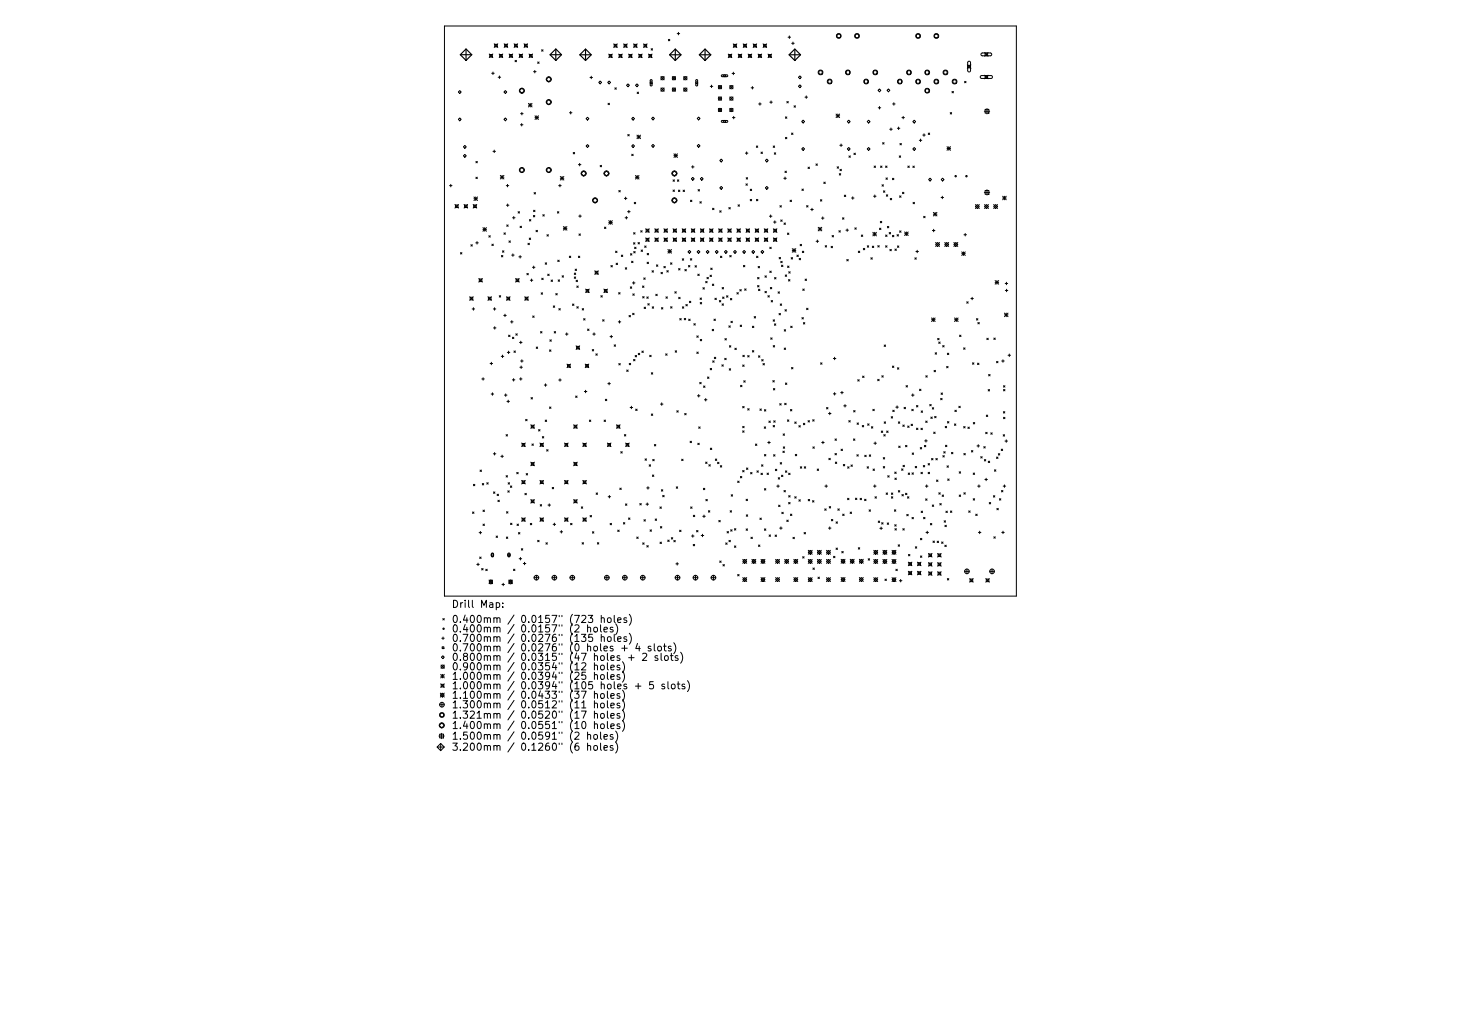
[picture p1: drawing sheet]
<svg xmlns="http://www.w3.org/2000/svg" width="297mm" height="210mm" viewBox="0 0 297 210" stroke-linecap="round" stroke-linejoin="round" font-family="sans-serif">
<defs><g id="words">
<g font-size="2">
<text x="91.8" y="123.6">Drill Map:</text>
<text x="91.8" y="126.7">0.400mm / 0.0157&quot; (723 holes)</text>
<text x="91.8" y="128.6">0.400mm / 0.0157&quot; (2 holes)</text>
<text x="91.8" y="130.5">0.700mm / 0.0276&quot; (135 holes)</text>
<text x="91.8" y="132.4">0.700mm / 0.0276&quot; (0 holes + 4 slots)</text>
<text x="91.8" y="134.4">0.800mm / 0.0315&quot; (47 holes + 2 slots)</text>
<text x="91.8" y="136.3">0.900mm / 0.0354&quot; (12 holes)</text>
<text x="91.8" y="138.2">1.000mm / 0.0394&quot; (25 holes)</text>
<text x="91.8" y="140.1">1.000mm / 0.0394&quot; (105 holes + 5 slots)</text>
<text x="91.8" y="142.1">1.100mm / 0.0433&quot; (37 holes)</text>
<text x="91.8" y="144">1.300mm / 0.0512&quot; (11 holes)</text>
<text x="91.8" y="146.1">1.321mm / 0.0520&quot; (17 holes)</text>
<text x="91.8" y="148.2">1.400mm / 0.0551&quot; (10 holes)</text>
<text x="91.8" y="150.4">1.500mm / 0.0591&quot; (2 holes)</text>
<text x="91.8" y="152.6">3.200mm / 0.1260&quot; (6 holes)</text>
</g>
</g></defs>
<g fill="none" stroke="#000" stroke-width=".2">
<path d="M90.4 5.3h116.2v115.9h-116.2zM93.5 18.4l.3 .3-.3 .3-.3-.3zM99.5 11l.7 .7M99.6 11.1h.5v.5h-.5zM100 14.9h.5M100.2 11l-.7 .7M100.2 14.6v.6M100.5 8.9l.7 .7M100.6 9h.5v.5h-.5zM101.2 8.9l-.7 .7M101.3 15.7h.5M101.5 11l.7 .7"/>
<path d="M101.5 15.4v.6M101.6 11.1h.5v.5h-.5zM102.2 11l-.7 .7M102.5 8.9l.7 .7M102.6 9h.5v.5h-.5zM102.7 18.4l.3 .3-.3 .3-.2-.3zM103.2 8.9l-.7 .7M103.5 11l.7 .7M103.6 11.1h.5v.5h-.5zM104.2 11l-.7 .7M104.5 8.9l.8 .7M104.6 9h.5v.5h-.5z"/>
<path d="M104.7 12.3l.3 .3M105 12.3l-.3 .3M105.3 8.9l-.8 .7M105.5 11l.8 .7M105.6 18.4l.5-.5 .5 .5-.5 .6zM105.6 11.1h.6v.5h-.6zM106.3 11l-.8 .7M106.5 8.9l.8 .7M106.7 9h.5v.5h-.5zM107.3 8.9l-.8 .7M107.6 11l.7 .7M107.7 11.1h.5v.5h-.5z"/>
<path d="M108.3 11l-.7 .7M108.5 14.6h.5M108.7 14.3v.5M109.3 12.6l.3 .3M109.6 12.6l-.3 .3M110.1 10.1l.3 .3M110.4 10.1l-.3 .3M111.1 16.1l.5-.5 .5 .5-.5 .5zM120 15.8h.5M120.2 15.5v.5M121.7 16.8l.3-.3 .3 .3-.3 .3zM123.5 16.8l.3-.3 .3 .3-.3 .3z"/>
<path d="M123.8 11l.7 .7M123.9 11.1h.5v.5h-.5zM124.5 11l-.7 .7M124.8 8.9l.7 .8M124.9 9h.5v.5h-.5zM125 17.9l.3 .2M125.3 17.9l-.3 .2M125.5 8.9l-.7 .8M125.8 11l.7 .7M125.9 11.1h.5v.5h-.5zM126.5 11l-.7 .7M126.8 8.9l.7 .8"/>
<path d="M126.9 9h.5v.5h-.5zM127.5 8.9l-.7 .8M127.7 17.1l.3 .2-.3 .3-.3-.3zM127.8 11l.7 .7M127.9 11.1h.5v.5h-.5zM128.5 11l-.7 .7M128.8 8.9l.7 .8M128.9 9h.5v.5h-.5zM129.5 17.1l.3 .2-.3 .3-.3-.3zM129.5 18.7l.3 .3M129.5 8.9l-.7 .8M129.8 18.7l-.3 .3"/>
<path d="M129.8 11l.8 .7M129.9 11.1h.6v.5h-.6zM130.6 11l-.8 .7M130.8 8.9l.8 .8M130.9 9h.6v.5h-.6zM131.6 8.9l-.8 .8M131.8 11l.8 .7M132 11.1h.5v.5h-.5zM132.2 16.6h.4v.4h-.4zM132.3 16.2h.1l.2 .1v1l-.2 .2-.2-.2zM132.4 9.9l.3 .3M132.6 11l-.8 .7"/>
<path d="M132.7 9.9l-.3 .3M134.4 15.6l.6 .6M134.4 17.9l.6 .6M135 15.6l-.6 .6M135 17.9l-.6 .6M135.9 8l.3 .3M136.2 8l-.3 .3M136.7 17.9l.6 .6M136.7 15.6l.6 .6M137.3 17.9l-.6 .6M137.3 15.6l-.6 .6M137.7 6.8h.5"/>
<path d="M137.9 6.6v.5M139 17.9l.7 .6M139 15.6l.7 .6M139.7 15.6l-.7 .6M139.7 17.9l-.7 .6M141.5 16.6h.3v.4h-.3zM141.5 16.2h.2l.1 .1v1l-.1 .2-.2-.2zM144.4 17.6h.5M144.7 17.3v.5M146.1 19.7l.6 .7M146.1 17.4l.6 .7M146.7 15.3l1.1-.1 .2 .2-.2 .2h-1l-.1-.1z"/>
<path d="M146.7 17.4l-.6 .7M146.7 19.7l-.6 .7M147.1 15.2h.4v.4h-.4zM148.1 11l.7 .7M148.2 11.1h.5v.5h-.5zM148.4 19.7l.6 .7M148.4 17.4l.6 .7M148.8 11l-.7 .7M148.8 14.9h.6M149 17.4l-.6 .7M149 19.7l-.6 .7M149.1 8.9l.7 .8"/>
<path d="M149.1 14.7v.5M149.2 9h.5v.5h-.5zM149.8 8.9l-.7 .8M150.1 11l.7 .7M150.2 11.1h.5v.5h-.5zM150.8 11l-.7 .7M151.1 8.9l.7 .8M151.2 9h.5v.5h-.5zM151.8 8.9l-.7 .8M152.1 11l.7 .7M152.2 11.1h.5v.5h-.5zM152.7 17.9h.5"/>
<path d="M152.8 11l-.7 .7M153 17.6v.5M153.1 8.9l.7 .8M153.2 9h.5v.5h-.5zM153.8 8.9l-.7 .8M154.1 11l.8 .7M154.2 11.1h.6v.5h-.6zM154.9 11l-.8 .7M155.1 8.9l.8 .8M155.2 9h.6v.5h-.6zM155.9 8.9l-.8 .8M156.2 11l.7 .7"/>
<path d="M156.3 11.1h.5v.5h-.5zM156.9 11l-.7 .7M160.2 7.6h.5M160.5 7.3v.5M161 8.8h.5M161.2 8.5v.6M162.3 15.7l.3-.3 .3 .3-.3 .3zM162.3 17.5l.3-.3 .3 .3-.3 .3zM163.7 19.8h.5M163.9 19.5v.5M166.5 14.4h.7v.7h-.7zM168.3 16.2h.7v.7h-.7z"/>
<path d="M170.2 7h.7v.6h-.7zM172 14.4h.7v.7h-.7zM173.9 7h.7v.6h-.7zM175.8 16.2h.6v.7h-.6zM177.6 14.4h.7v.7h-.7zM178.8 18.1l.3 .3-.3 .3-.3-.3zM180.6 18.1l.3 .3-.3 .3-.3-.3zM182.6 16.2h.7v.7h-.7zM184.5 14.4h.6v.7h-.6zM186.3 7h.7v.7h-.7zM186.3 16.2h.7v.7h-.7zM188.2 14.4h.7v.7h-.7z"/>
<path d="M188.2 18.1h.7v.7h-.7zM190 7h.7v.7h-.7zM190 16.2h.7v.7h-.7zM191.9 14.4h.7v.7h-.7zM193.6 18.6l.2 .3M193.7 16.2h.7v.7h-.7zM193.8 18.6l-.2 .3M196.1 16.5l.3 .3M196.4 16.5l-.3 .3M196.7 13.2l.7 .7M196.8 13.3h.5v.5h-.5zM196.8 12.5h.3l.2 .2v1.7l-.2 .2-.4-.2z"/>
<path d="M197.4 13.2l-.7 .7M199.4 15.5l2.1-.1 .3 .3-.3 .2h-1.9l-.3-.1zM199.5 10.9l1.9-.1 .2 .3-.2 .2h-1.7l-.2-.1zM200.2 10.7l.7 .7M200.2 15.3l.7 .7M200.3 10.8h.5v.5h-.5zM200.3 15.4h.5v.5h-.5zM200.9 10.7l-.7 .7M200.9 15.3l-.7 .7M91.4 37.7h.5M91.6 37.5v.5M93.2 24.3l.3-.3 .3 .3-.3 .3z"/>
<path d="M94.2 31.7l.3-.3 .3 .3-.3 .3zM94.5 29.6l.3 .3-.3 .3-.3-.3zM96.8 32.8l.3 .3M96.8 36l.3 .3M97.1 32.8l-.3 .3M97.1 36l-.3 .3M100.2 30.8h.5M100.5 30.5v.5M101.7 35.7l.8 .7M101.7 36h.8M102.1 35.7v.7M102.5 24.3l.2-.3 .3 .3-.3 .3z"/>
<path d="M102.5 35.7l-.8 .7M102.9 37.7h.5M103.2 37.5v.5M105.6 34.6l.5-.5 .5 .5-.5 .5zM105.8 25.4h.5M105.8 23.1h.6M106.1 25.1v.5M106.1 22.9v.5M107.4 21l.8 .7M107.4 21.4h.8M107.8 21v.7M108.2 21l-.8 .7"/>
<path d="M108.6 39.2l.3 .2M108.8 23.9h.7M108.8 23.5l.7 .8M108.9 39.2l-.3 .2M109.1 23.5v.8M109.5 23.5l-.7 .8M111.1 20.8l.5-.5 .5 .5-.5 .5zM111.1 34.6l.5-.5 .5 .5-.5 .5zM113.6 37.7h.5M113.8 37.5v.5M113.9 36.3h.7M113.9 35.9l.7 .7"/>
<path d="M114.3 35.9v.7M114.6 35.9l-.7 .7M115.8 22.9h.5M116 22.7v.5M116.5 31l.3 .3M116.8 31l-.3 .3M117.6 33.5h.5M117.9 33.2v.5M118.7 34.8l.5 .5-.5 .5-.5-.5zM119.2 24.1l.2-.3 .3 .3-.3 .3zM119.2 29.7l.2-.3 .3 .3-.3 .3zM122 33.6l.3 .3"/>
<path d="M122.3 33.6l-.3 .3M123.3 34.8l.5 .5-.5 .5-.5-.5zM123.6 21l.3 .3M123.9 21l-.3 .3M125.8 38.7l.3 .3M126.1 38.7l-.3 .3M127.6 27.3l.3 .3M127.9 27.3l-.3 .3M128.4 24.1l.3-.3 .3 .3-.3 .3zM128.4 29.7l.3-.3 .3 .3-.3 .3zM128.4 31.4l.3 .3M128.7 31.4l-.3 .3"/>
<path d="M129.2 36.1h.7M129.2 35.7l.7 .7M129.5 27.5l.7 .7M129.5 27.8h.7M129.6 35.7v.7M129.9 27.5v.7M129.9 35.7l-.7 .7M130.2 27.5l-.7 .7M132.5 29.7l.3-.3 .3 .3-.3 .2zM132.8 23.8l.3 .3-.3 .3-.3-.3zM136.8 36.6l.3 .3M136.8 38.6l.3 .3"/>
<path d="M137 31.3l.7 .7M137 31.6h.7M137.1 34.8l.5 .5-.5 .5-.5-.5zM137.1 38.6l-.3 .3M137.1 36.6l-.3 .3M137.4 31.3v.7M137.7 36.6l.3 .3M137.7 31.3l-.7 .7M137.9 38.7l.3 .3M138 36.6l-.3 .3M138.2 38.7l-.3 .3M138.9 38.7l.3 .3"/>
<path d="M139.2 38.7l-.3 .3M140.6 33.9h.5M140.9 36.1l.2 .3-.2 .3-.3-.3zM140.9 33.7v.5M141.7 29.7l.3-.3 .3 .3-.3 .2zM141.9 38.6l.3 .2M142 23.8l.3 .3-.3 .3-.3-.3zM142.2 38.6l-.3 .2M142.7 36.1l.3 .3-.3 .3-.3-.3zM146.1 22l.6 .7M146.6 32.3l.3 .3-.3 .3-.3-.3zM146.6 37.9l.3 .3-.3 .3-.3-.3z"/>
<path d="M146.7 24.6l1.1-.1 .2 .2-.2 .2h-1l-.1-.2zM146.7 22l-.6 .7M147.1 24.5h.4v.4h-.4zM148.4 22l.6 .7M148.9 23.9h.5M149 22l-.6 .7M149.2 23.7v.5M151.5 31.1h.6M151.7 37.4l.2 .3M151.7 36.1l.3 .3M151.8 30.9v.5M151.9 37.4l-.2 .3"/>
<path d="M152 36.1l-.3 .3M152.5 38.5l.3 .3M152.8 38.5l-.3 .3M153.8 29.7l.3 .3M154.1 29.7l-.3 .3M154.2 21.1h.6M154.5 20.9v.5M154.7 30.9l.3 .3M155 30.9l-.3 .3M155.9 32.3l.3 .3-.3 .3-.3-.3zM155.9 37.9l.3 .3-.3 .3-.3-.3zM156.5 20.8h.5"/>
<path d="M156.8 20.5v.5M157.2 29.7l.3 .3M157.4 31.1l.3 .3M157.5 29.7l-.3 .3M157.7 31.1l-.3 .3M159.4 36.3h.5M159.6 34.8l.3 .3M159.6 36v.5M159.7 23.8l.3 .3M159.7 27.9l.3 .3M159.9 34.8l-.3 .3M160 23.8l-.3 .3"/>
<path d="M160 20.6l.3 .3M160 27.9l-.3 .3M160.3 20.6l-.3 .3M160.9 27.1l.3 .2M161.2 27.1l-.3 .2M161.4 21.5l.3 .3M161.7 21.5l-.3 .3M163 24.7l.3-.3 .3 .3-.3 .3zM163 30.3l.3-.3 .3 .3-.3 .3zM163 38.4l.3 .3M163.3 38.4l-.3 .3M164.3 34l.3 .3"/>
<path d="M164.6 34l-.3 .3M165.9 33.3l.3 .3M166.2 33.3l-.3 .3M167.5 37l.3 .3M167.8 37l-.3 .3M170 23.2l.7 .7M170 23.5h.7M170.2 33.9l.3 .3M170.3 23.2v.7M170.5 33.9l-.3 .3M170.6 35.3l.3 .3M170.7 23.2l-.7 .7"/>
<path d="M170.7 29.5h.6M170.8 34.4l.3 .3M170.9 35.3l-.3 .3M171 29.3v.5M171.1 34.4l-.3 .3M171.7 39.7l.2 .3M171.9 39.7l-.2 .3M172.3 24.7l.3-.3 .3 .3-.3 .3zM172.3 30.3l.3-.3 .3 .3-.3 .3zM172.6 31.7l.3 .3M172.9 31.7l-.3 .3M173.6 31.1l.3 .3"/>
<path d="M173.9 31.1l-.3 .3M176.3 24.7l.3-.3 .3 .3-.3 .3zM176.3 30.3l.3-.3 .3 .3-.3 .3zM177.6 39.9h.5M177.7 33.8l.3 .3M177.9 39.6v.6M178 33.8l-.3 .3M178.6 21.9h.5M178.8 21.7v.5M179 33.8l.3 .3M179.3 33.8l-.3 .3M179.3 37.6l.3 .3"/>
<path d="M179.4 29l.3 .3M179.6 37.6l-.3 .3M179.6 38.8l.3 .3M179.7 29l-.3 .3M179.9 38.8l-.3 .3M180.1 33.8l.2 .3M180.1 36.2l.3 .3M180.2 39.6l.3 .3M180.3 33.8l-.2 .3M180.4 36.2l-.3 .3M180.5 39.6l-.3 .3M180.9 26.3h.5"/>
<path d="M181.1 26v.5M181.4 36.3l.3 .2M181.5 21.1h.5M181.7 36.3l-.3 .2M181.7 20.9v.5M182.4 26.1h.6M182.7 25.8v.5M182.8 31.7l.3 .3M182.9 39.8l.3 .3M183 29.2l.3 .3M183.1 31.7l-.3 .3M183.2 39.8l-.3 .3"/>
<path d="M183.3 29.2l-.3 .3M183.4 23.9h.5M183.5 39.1l.3 .3M183.6 23.7v.5M183.8 39.1l-.3 .3M184.6 33.8l.3 .3M184.9 33.8l-.3 .3M185.6 24.7l.3-.3 .3 .3-.3 .3zM185.6 30.3l.3-.3 .3 .3-.3 .3zM185.6 33.8l.3 .3M185.9 33.8l-.3 .3M186.9 28.5h.5"/>
<path d="M187.2 28.3v.5M187.6 27.5h.5M187.9 27.2v.5M188.7 27.1l.3 .3M188.8 36.5l.3-.3 .3 .3-.3 .3zM189 27.1l-.3 .3M191.4 36.5l.2-.3 .3 .3-.3 .3zM191.6 39.9v.5M192.5 29.8l.8 .8M192.5 30.2h.8M192.9 29.8v.8M193.2 22.9l.3 .3"/>
<path d="M193.3 29.8l-.8 .8M193.5 22.9l-.3 .3M200.1 22.6h1.1M200.1 39.1h1.1M200.3 22.2h.8v.8h-.8zM200.3 38.7h.8v.8h-.8zM200.7 22.1v1.1M200.7 38.6v1.1M203.8 39.9l.8 .7M204.2 39.9v.7M204.6 39.9l-.8 .7M92.5 41.6l.7 .7"/>
<path d="M92.6 41.7h.5v.5h-.5zM93.2 41.6l-.7 .7M93.6 51.4l.3 .3M93.9 51.4l-.3 .3M94.3 41.6l.8 .7M94.5 41.7h.5v.5h-.5zM95.1 41.6l-.8 .7M95.7 49.8l.3 .2M96 49.8l-.3 .2M96.2 41.6l.7 .7M96.3 41.7h.5v.5h-.5zM96.4 40l.7 .8"/>
<path d="M96.4 40.4h.7M96.7 40v.8M96.7 49.4h.5M96.9 41.6l-.7 .7M97 49.1v.5M97.1 40l-.7 .8M97.3 56.6l.8 .8M97.4 56.7h.6v.6h-.6zM98.1 56.6l-.8 .8M98.2 46.3l.7 .7M98.2 46.7h.7M98.5 46.3v.7"/>
<path d="M98.9 46.3l-.7 .7M99.4 47.9l.3 .3M99.7 47.9l-.3 .3M100 49.6l.3 .3M100.3 49.6l-.3 .3M101.9 51.9l.3 .3M102.2 51l.3 .3M102.2 51.9l-.3 .3M102.5 51l-.3 .3M102.5 47.4l.2 .2M102.7 47.4l-.2 .2M103 41.7h.5"/>
<path d="M103 45.7l.3 .3M103.2 41.5v.5M103.3 45.7l-.3 .3M103.5 49l.3 .3M103.8 49l-.3 .3M104 51.9h.5M104.2 44.3h.5M104.3 51.6v.5M104.5 44v.5M104.8 56.6l.8 .8M104.9 56.7h.6v.6h-.6zM105.3 43l.3 .3"/>
<path d="M105.5 52.2h.5M105.6 56.6l-.8 .8M105.6 43l-.3 .3M105.7 46l.3 .3M105.7 52v.5M106 46l-.3 .3M107.1 55.6l.3 .3M107.3 49.5l.3 .3M107.4 55.6l-.3 .3M107.6 48.4l.3 .3M107.6 49.5l-.3 .3M107.6 44.6l.3 .3"/>
<path d="M107.8 57h.5M107.9 48.4l-.3 .3M107.9 44.6l-.3 .3M108.1 56.7v.5M108.3 54.4h.5M108.4 43.8l.3 .3M108.5 42.7l.3 .3M108.5 54.1v.5M108.7 43.8l-.3 .3M108.8 42.7l-.3 .3M109 46.8l.3 .3M109.3 46.8l-.3 .3"/>
<path d="M110 59.5l.3 .3M110.1 56.6l.3 .3M110.3 59.5l-.3 .3M110.4 43.7l.3 .2M110.4 56.6l-.3 .3M110.7 43.7l-.3 .2M110.8 53.4l.3 .3M111.1 53.4l-.3 .3M111.2 47.7l.3 .3M111.4 55.7l.3 .3M111.5 47.7l-.3 .3M111.7 55.7l-.3 .3"/>
<path d="M112 56.9l.3 .3M112.3 56.9l-.3 .3M113 59.7l.3 .3M113.3 59.7l-.3 .3M113.3 43l.3 .3M113.4 52.9l.3 .3M113.5 56.9l.3 .3M113.6 43l-.3 .3M113.7 52.9l-.3 .3M113.8 56.9l-.3 .3M114.3 56.1l.3 .3M114.5 46.1l.8 .7"/>
<path d="M114.5 46.4h.8M114.6 56.1l-.3 .3M114.9 46.1v.7M115.3 46.1l-.8 .7M115.8 52.1l.2 .3M116 52.1l-.2 .3M116.8 56.3l.2 .3M116.8 55.5l.3 .3M116.9 54.7l.3 .3M117 56.3l-.2 .3M117.1 55.5l-.3 .3M117.1 57l.3 .3"/>
<path d="M117.2 54.7l-.3 .3M117.3 58.2l.3 .2M117.4 57l-.3 .3M117.6 58.2l-.3 .2M117.6 52.1l.3 .3M117.7 43.9h.5M117.7 47.6l.3 .3M117.9 52.1l-.3 .3M117.9 43.7v.5M118 47.6l-.3 .3M119.1 58.8l.7 .7M119.2 58.9h.5v.5h-.5z"/>
<path d="M119.8 58.8l-.7 .7M120.9 55.1l.8 .7M121 40.2l.5 .5-.5 .5-.5-.5zM121 55.2h.5v.5h-.5zM121.7 55.1l-.8 .7M122.8 58.8l.7 .7M122.9 58.9h.5v.5h-.5zM122.9 46.2l.3 .3M123.2 46.2l-.3 .3M123.5 58.8l-.7 .7M123.8 44.9l.7 .7M123.8 45.2h.7"/>
<path d="M124.1 44.9v.7M124.2 54l.3 .3M124.5 54l-.3 .3M124.5 44.9l-.7 .7M125.2 51.1l.2 .3M125.3 53.5l.3 .3M125.4 51.1l-.2 .3M125.6 53.5l-.3 .3M125.8 59.5l.3 .3M126.1 59.5l-.3 .3M126.3 51.9l.3 .3M126.6 51.9l-.3 .3"/>
<path d="M126.9 40.3h.6M127.1 44.3h.5M127.1 54.4l.3 .3M127.2 40.1v.5M127.3 44v.5M127.4 54.4l-.3 .3M127.6 43h.5M127.9 42.8v.5M128.1 58.3l.3 .3M128.2 51.6l.3 .3M128.4 53.1l.3 .3M128.4 58.3l-.3 .3"/>
<path d="M128.5 51.6l-.3 .3M128.6 57.5h.5M128.7 59.8l.3 .2M128.7 53.1l-.3 .3M128.8 49.4l.3 .2M128.8 47.3l.3 .3M128.8 51.1l.3 .3M128.8 57.3v.5M129 59.8l-.3 .2M129 41.1l.2 .3M129 50.3l.3 .3M129.1 49.4l-.3 .2"/>
<path d="M129.1 47.3l-.3 .3M129.1 51.1l-.3 .3M129.2 41.1l-.2 .3M129.3 50.3l-.3 .3M129.7 49.3l.3 .3M130 49.3l-.3 .3M130.3 46.9l.3 .3M130.3 50.8l.3 .3M130.6 46.9l-.3 .3M130.6 58.2l.3 .2M130.6 50.8l-.3 .3M130.9 56.5l.3 .3"/>
<path d="M130.9 58.2l-.3 .2M131.1 50l.3 .3M131.2 56.5l-.3 .3M131.3 46.5l.7 .7M131.3 48.4l.7 .7M131.4 50l-.3 .3M131.4 46.6h.5v.5h-.5zM131.4 48.5h.5v.5h-.5zM131.6 53.3l.3 .3M131.6 51.5l.3 .3M131.9 53.3l-.3 .3M131.9 51.5l-.3 .3"/>
<path d="M132 48.4l-.7 .7M132 46.5l-.7 .7M132.6 55l.3 .3M132.9 55l-.3 .3M133.1 46.5l.8 .7M133.1 48.4l.8 .7M133.2 46.6h.5v.5h-.5zM133.2 48.5h.5v.5h-.5zM133.3 59.8l.3 .3M133.5 53.9l.3 .3M133.6 59.8l-.3 .3M133.8 53.9l-.3 .3"/>
<path d="M133.9 46.5l-.8 .7M133.9 48.4l-.8 .7M134.4 55.4l.3 .3M134.7 55.4l-.3 .3M135 54.2l.3 .3M135 46.5l.7 .7M135 48.4l.7 .7M135.1 46.6h.5v.5h-.5zM135.1 48.5h.5v.5h-.5zM135.3 54.2l-.3 .3M135.6 55l.3 .3M135.7 46.5l-.7 .7"/>
<path d="M135.7 48.4l-.7 .7M135.8 50.7l.7 .8M135.8 51.1h.7M135.9 55l-.3 .3M136.2 50.7v.8M136.3 53.4l.3 .3M136.5 50.7l-.7 .8M136.6 53.4l-.3 .3M136.8 48.4l.8 .7M136.8 46.5l.8 .7M136.9 46.6h.6v.5h-.6zM136.9 48.5h.6v.5h-.6z"/>
<path d="M137.1 40.2l.5 .5-.5 .5-.5-.5zM137.2 59.3l.3 .3M137.5 59.3l-.3 .3M137.6 48.4l-.8 .7M137.6 46.5l-.8 .7M138 54.6l.3 .3M138.3 54.6l-.3 .3M138.7 48.4l.7 .7M138.7 46.5l.7 .7M138.7 52.6l.3 .3M138.8 46.6h.5v.5h-.5zM138.8 48.5h.5v.5h-.5z"/>
<path d="M139 52.6l-.3 .3M139.2 54.8l.3 .3M139.4 48.4l-.7 .7M139.4 46.5l-.7 .7M139.5 54.8l-.3 .3M140 54l.3 .3M140.2 50.9l.3 .3-.3 .3-.3-.3zM140.3 54l-.3 .3M140.4 52.6l.2 .3M140.4 40.7l.3 .3M140.5 48.4l.8 .7M140.5 46.5l.8 .7"/>
<path d="M140.6 52.6l-.2 .3M140.7 46.6h.5v.5h-.5zM140.7 48.5h.5v.5h-.5zM140.7 40.7l-.3 .3M141.3 46.5l-.8 .7M141.3 48.4l-.8 .7M141.3 54l.3 .3M141.6 54l-.3 .3M141.9 55.7l.3 .3M142 50.9l.3 .3-.3 .3-.3-.3zM142.2 55.7l-.3 .3M142.3 41l.3 .3"/>
<path d="M142.4 48.4l.7 .7M142.4 46.5l.7 .7M142.5 46.6h.5v.5h-.5zM142.5 48.5h.5v.5h-.5zM142.6 41l-.3 .3M142.9 58.5l.3 .3M143.1 46.5l-.7 .7M143.1 48.4l-.7 .7M143.2 58.5l-.3 .3M143.5 57.2l.3 .3M143.7 56.4l.3 .3M143.8 57.2l-.3 .3"/>
<path d="M143.9 50.9l.3 .3-.3 .3-.3-.3zM144 56.4l-.3 .3M144.3 46.5l.7 .7M144.3 48.4l.7 .7M144.4 55.9l.2 .3M144.4 46.6h.5v.5h-.5zM144.4 48.5h.5v.5h-.5zM144.5 54.5l.3 .3M144.6 55.9l-.2 .3M144.8 54.5l-.3 .3M144.8 57.8l.3 .3M144.9 42.3l.3 .3"/>
<path d="M145 48.4l-.7 .7M145 46.5l-.7 .7M145.1 57.8l-.3 .3M145.2 42.3l-.3 .3M145.7 50.9l.3 .3-.3 .3-.3-.3zM146.1 48.4l.7 .7M146.1 46.5l.7 .7M146.2 46.6h.5v.5h-.5zM146.2 48.5h.5v.5h-.5zM146.3 42.9l.3 .2M146.5 52.1l.3 .3M146.6 42.9l-.3 .2"/>
<path d="M146.8 52.1l-.3 .3M146.8 58.5l.3 .3M146.8 46.5l-.7 .7M146.8 48.4l-.7 .7M147.1 58.5l-.3 .3M147.6 50.9l.3 .3-.3 .3-.3-.3zM148 48.4l.7 .7M148 46.5l.7 .7M148.1 46.6h.5v.5h-.5zM148.1 48.5h.5v.5h-.5zM148.2 42.2l.3 .3M148.4 51.9l.3 .3"/>
<path d="M148.5 42.2l-.3 .3M148.7 51.9l-.3 .3M148.7 46.5l-.7 .7M148.7 48.4l-.7 .7M149.4 50.9l.3 .3-.3 .3-.3-.3zM149.8 48.4l.7 .7M149.8 46.5l.7 .7M149.8 59.5l.3 .3M149.9 46.6h.5v.5h-.5zM149.9 48.5h.5v.5h-.5zM150 41.6l.3 .3M150.1 59.5l-.3 .3"/>
<path d="M150.3 41.6l-.3 .3M150.4 58.9l.3 .3M150.5 46.5l-.7 .7M150.5 48.4l-.7 .7M150.7 58.9l-.3 .3M151.1 54l.3 .3M151.3 50.9l.3 .3-.3 .3-.3-.3zM151.4 58.7l.3 .3M151.4 54l-.3 .3M151.7 48.4l.7 .7M151.7 46.5l.7 .7M151.7 58.7l-.3 .3"/>
<path d="M151.8 46.6h.5v.5h-.5zM151.8 48.5h.5v.5h-.5zM152.4 46.5l-.7 .7M152.4 48.4l-.7 .7M152.5 40.5l.3 .3M152.8 40.5l-.3 .3M153.1 50.9l.3 .3-.3 .3-.3-.3zM153.5 46.5l.8 .7M153.5 48.4l.8 .7M153.6 46.6h.5v.5h-.5zM153.6 48.5h.5v.5h-.5zM153.8 40.5l.3 .3"/>
<path d="M153.8 52.1l.3 .3M154 58.1l.3 .3M154 56.4l.3 .3M154.1 40.5l-.3 .3M154.1 52.1l-.3 .3M154.1 54.2l.3 .3M154.2 58.8l.3 .3M154.3 48.4l-.8 .7M154.3 46.5l-.8 .7M154.3 58.1l-.3 .3M154.3 56.4l-.3 .3M154.4 54.2l-.3 .3"/>
<path d="M154.5 58.8l-.3 .3M155 50.9l.3 .3-.3 .3-.3-.3zM155.4 48.4l.7 .7M155.4 46.5l.7 .7M155.5 46.6h.5v.5h-.5zM155.5 48.5h.5v.5h-.5zM155.5 56.1l.3 .3M155.5 59.2l.3 .3M155.8 56.1l-.3 .3M155.8 59.2l-.3 .3M156.1 48.4l-.7 .7M156.1 46.5l-.7 .7"/>
<path d="M156.4 44h.5M156.5 50.3l.3 .3M156.5 55.1l.3 .3M156.6 58.4l.3 .3M156.7 43.7v.5M156.8 55.1l-.3 .3M156.8 50.3l-.3 .3M156.9 58.4l-.3 .3M157.2 48.4l.8 .7M157.2 46.5l.8 .7M157.3 45.2h.5M157.3 46.6h.6v.5h-.6z"/>
<path d="M157.3 48.5h.6v.5h-.6zM157.5 56.4l.3 .3M157.5 44.9v.5M157.8 56.4l-.3 .3M158 46.5l-.8 .7M158 48.4l-.8 .7M158.2 59.3l.3 .3M158.4 52.3l.3 .3M158.5 59.3l-.3 .3M158.6 41.8l.3 .3M158.7 52.3l-.3 .3M158.7 44.7l.3 .3"/>
<path d="M158.7 53.1l.3 .3M158.9 41.8l-.3 .3M158.9 53.9l.3 .3M159 44.7l-.3 .3M159 53.1l-.3 .3M159.2 53.9l-.3 .3M159.4 45.3l.3 .3M159.6 55.9l.3 .3M159.7 45.3l-.3 .3M159.9 55.9l-.3 .3M160.1 47.4l.3 .3M160.1 54.1l.3 .3"/>
<path d="M160.3 56.9l.3 .2M160.4 55.2l.3 .3M160.4 47.4l-.3 .3M160.4 54.1l-.3 .3M160.6 56.9l-.3 .2M160.6 40.7l.3 .3M160.7 55.2l-.3 .3M160.9 52.4l.2 .3M160.9 40.7l-.3 .3M161.1 50.6l.7 .7M161.1 50.9h.7M161.1 52.4l-.2 .3"/>
<path d="M161.4 50.6v.7M161.8 50.6l-.7 .7M162 51.9l.3 .3M162.3 51.9l-.3 .3M162.5 52.5l.3 .3M162.7 49.7l.3 .3M162.8 52.5l-.3 .3M163 49.7l-.3 .3M163.1 51.1l.3 .3M163.2 58.8l.3 .3M163.4 51.1l-.3 .3M163.5 58.8l-.3 .3"/>
<path d="M163.7 56.7l.3 .3M164 56.7l-.3 .3M164 41.8l.3 .3M164.3 41.8l-.3 .3M164.8 42.6h.5M165.1 42.3v.6M165.9 49.1h.5M166.2 48.8v.5M166.3 46.2l.8 .7M166.3 46.6h.8M166.7 46.2v.7M166.8 40.6l.3 .3"/>
<path d="M167 44.4h.5M167.1 46.2l-.8 .7M167.1 40.6l-.3 .3M167.3 44.1v.5M167.8 49.9l.3 .3M168.1 49.9l-.3 .3M169 50.1l.3 .3M169.2 47.9l.3 .3M169.3 50.1l-.3 .3M169.5 47.9l-.3 .3M170.6 46.9l.3 .3M170.9 46.9l-.3 .3"/>
<path d="M171.3 44.3l.3 .3M171.6 44.3l-.3 .3M172 46.8h.5M172.2 52.8l.3 .3M172.2 46.5v.6M172.5 52.8l-.3 .3M173.1 40.3h.5M173.4 40v.5M173.8 46.3l.3 .3M174.1 46.3l-.3 .3M174.5 51.1l.3 .3M174.8 51.1l-.3 .3"/>
<path d="M175.1 47.8l.3 .3M175.4 47.8l-.3 .3M175.5 50.5l.3 .3M175.8 50.5l-.3 .3M176.3 50l.3 .3M176.6 50l-.3 .3M177.1 52.4l.3 .3M177.4 50l.2 .3M177.4 52.4l-.3 .3M177.5 47.2l.7 .8M177.5 47.6h.7M177.6 50l-.2 .3"/>
<path d="M177.8 47.2v.8M178.2 47.2l-.7 .8M178.5 49.9l.3 .3M178.8 49.9l-.3 .3M178.8 46.4l.3 .3M179 45l.3 .3M179.1 46.4l-.3 .3M179.3 45l-.3 .3M180.1 50l.2 .3M180.1 47.8l.2 .3M180.3 50l-.2 .3M180.3 47.8l-.2 .3"/>
<path d="M180.4 46l.3 .3M180.7 46l-.3 .3M180.8 47.3l.3 .3M180.9 50.7l.3 .3M181 40.3l.3 .3M181.1 47.3l-.3 .3M181.2 50.7l-.3 .3M181.3 40.3l-.3 .3M181.4 47.9l.3 .3M181.7 47.9l-.3 .3M181.9 50.6l.3 .3M182.2 50.6l-.3 .3"/>
<path d="M182.4 47.7l.3 .3M182.5 50l.3 .3M182.7 47.7l-.3 .3M182.8 50l-.3 .3M182.9 46.9l.3 .3M183.2 46.9l-.3 .3M183.9 47.2l.8 .7M183.9 47.5h.8M184.3 47.2v.7M184.7 47.2l-.8 .7M185.6 41.1l.3 .3M185.9 41.1l-.3 .3"/>
<path d="M186 52.4l.3 .3M186.2 51.1h.5M186.3 52.4l-.3 .3M186.5 50.9v.5M187.8 44l.3 .3M188.1 44l-.3 .3M189.6 46.9h.5M189.8 43.2l.7 .7M189.8 43.6h.7M189.8 46.6v.5M190.1 43.2v.7M190.2 49.7l.4-.4 .4 .4-.4 .4z"/>
<path d="M190.2 49.3l.8 .8M190.5 43.2l-.7 .7M191 49.3l-.8 .8M191.3 40.2h.5M192.1 49.7l.4-.4 .4 .4-.4 .4zM192.1 49.3l.8 .8M192.9 49.3l-.8 .8M193.9 49.7l.4-.4 .4 .4-.4 .4zM193.9 49.3l.8 .8M194.7 49.3l-.8 .8M195.5 51.2l.8 .7M195.5 51.6h.8"/>
<path d="M195.9 51.2v.7M196 47.7h.5M196.2 47.5v.5M196.3 51.2l-.8 .7M198.3 42l.4-.4 .4 .4-.4 .4zM198.3 41.6l.8 .8M199.1 41.6l-.8 .8M200.2 42l.4-.4 .4 .4-.4 .4zM200.2 41.6l.8 .8M201 41.6l-.8 .8M202 42l.4-.4 .4 .4-.4 .4zM202 41.6l.8 .8"/>
<path d="M202.3 57.1l.7 .7M202.3 57.4h.7M202.7 57.1v.7M202.8 41.6l-.8 .8M203 57.1l-.7 .7M203.8 40.3h.8M204.4 57.6h.5M204.4 59.1h.5M204.6 57.4v.5M204.7 58.8v.5M95.5 60.3l.7 .8M95.6 60.4h.5v.6h-.5z"/>
<path d="M96 62.8h.5M96.2 60.3l-.7 .8M96.2 62.6v.5M98 77.1h.5M98.2 76.8v.5M99.2 60.3l.7 .8M99.3 60.4h.5v.6h-.5zM99.6 73.9h.6M99.9 73.7v.5M99.9 60.3l-.7 .8M100.1 79.9v.5M100.3 62.8h.5"/>
<path d="M100.3 66.7h.5M100.6 62.6v.5M100.6 66.4v.5M101.5 60.1l.3 .3M101.8 60.1l-.3 .3M101.9 72.5h.5M102.2 72.2v.5M102.4 64.1h.5M102.7 63.9v.5M103 60.3l.7 .8M103.1 60.4h.5v.6h-.5zM103.1 71.7h.6"/>
<path d="M103.4 68.2l.3 .2M103.4 71.4v.5M103.7 68.2l-.3 .2M103.7 60.3l-.7 .8M103.8 65.5h.5M104.1 65.2v.5M104.2 77.2h.5M104.2 68.6l.3 .3M104.4 77v.5M104.5 68.6l-.3 .3M104.5 71.4l.3 .3M104.8 71.4l-.3 .3"/>
<path d="M104.9 67.9l.3 .3M105.2 67.9l-.3 .3M105.6 77.1h.5M105.6 69.6h.5M105.7 74.7h.5M105.8 73.4h.6M105.9 69.4v.5M105.9 76.8v.5M106 74.4v.5M106.1 73.2v.5M106.7 60.3l.7 .8M106.8 60.4h.5v.6h-.5z"/>
<path d="M107.4 60.3l-.7 .8M108.3 64.2l.3 .3M108.6 64.2l-.3 .3M109 70.6l.3 .3M109.3 70.6l-.3 .3M109.9 67.4l.3 .3M110.2 67.4l-.3 .3M110.7 78.3h.5M110.9 78v.6M111.7 71.1l.3 .3M111.8 69.1l.3 .3M112 71.1l-.3 .3"/>
<path d="M112.1 69.1l-.3 .3M112.5 62.2l.3 .3M112.7 67.4l.3 .3M112.8 62.2l-.3 .3M113 67.4l-.3 .3M113.6 77.3h.5M113.6 62.8l.3 .2M113.9 77v.5M113.9 62.8l-.3 .2M115 67.9h.5M115.2 67.7v.5M115.3 74l.7 .8"/>
<path d="M115.4 74.1h.5v.6h-.5zM116 74l-.7 .8M116.4 61.8l.3 .3M116.7 61.8l-.3 .3M117.1 70.3l.8 .8M117.2 70.4h.5v.5h-.5zM117.3 62.4l.3 .3M117.6 62.4l-.3 .3M117.9 70.3l-.8 .8M118.4 62.8l.3 .2M118.7 62.8l-.3 .2M118.7 64.8l.3 .3"/>
<path d="M118.8 79.6h.5M119 64.8l-.3 .3M119 74l.7 .8M119.1 79.4v.5M119.1 74.1h.5v.6h-.5zM119.5 66.9l.3 .3M119.7 74l-.7 .8M119.8 66.9l-.3 .3M120.4 71.1l.3 .3M120.5 67.9h.5M120.7 71.1l-.3 .3M120.8 67.7v.5"/>
<path d="M121.1 71.9l.3 .3M121.4 71.9l-.3 .3M122.2 60.1l.3 .3M122.5 60.1l-.3 .3M122.5 65l.3 .3M122.8 65l-.3 .3M123.6 78h.5M123.8 77.8v.5M124 68.4h.5M124.3 68.2v.5M124.9 70.1l.3 .3M125.2 70.1l-.3 .3"/>
<path d="M125.7 65.5h.5M125.8 73.9l.3 .3M126 65.2v.5M126.1 73.9l-.3 .3M127.4 75.2l.3 .3M127.7 75.2l-.3 .3M127.9 64.1l.3 .3M127.9 73.9l.3 .3M128.2 64.1l-.3 .3M128.2 73.9l-.3 .3M128.6 63.7l.3 .3M128.8 73.1l.3 .3"/>
<path d="M128.9 63.7l-.3 .3M129.1 73.1l-.3 .3M129.1 72.3l.3 .3M129.4 72.3l-.3 .3M129.8 71.8l.3 .3M130.1 71.8l-.3 .3M130.5 71.4l.3 .3M130.7 60.3l.3 .3M130.8 71.4l-.3 .3M131 60.3l-.3 .3M131 62.5l.3 .3M131.3 62.5l-.3 .3"/>
<path d="M131.5 60.4l.3 .3M131.7 61.7l.3 .3M131.8 60.4l-.3 .3M132 61.7l-.3 .3M132.1 72.2l.3 .3M132.4 72.2l-.3 .3M132.4 75.8l.3 .3M132.6 62.4l.3 .3M132.7 75.8l-.3 .3M132.9 62.4l-.3 .3M134.5 62.5l.3 .3M134.8 62.5l-.3 .3"/>
<path d="M135.3 71.9l.3 .3M135.4 60.4l.3 .3M135.6 71.9l-.3 .3M135.7 60.4l-.3 .3M136.3 62.4l.3 .3M136.6 62.4l-.3 .3M137.3 71.3l.3 .3M137.6 71.3l-.3 .3M138 60.5l.3 .2M138.2 64.8l.3 .3M138.3 60.5l-.3 .2M138.5 64.8l-.3 .3"/>
<path d="M138.7 62.4l.3 .3M139 62.4l-.3 .3M139.1 64.7l.3 .3M139.4 64.7l-.3 .3M139.4 61.9l.3 .3M139.7 61.9l-.3 .3M140 64.9l.3 .3M140.2 61.3l.2 .2M140.3 64.9l-.3 .3M140.4 61.3l-.2 .2M141.1 65.8l.3 .3M141.4 65.8l-.3 .3"/>
<path d="M141.7 68.3l.3 .3M141.7 71.6l.3 .3M142 68.3l-.3 .3M142 71.6l-.3 .3M142.3 77.8l.3 .2M142.3 60.6l.3 .3M142.4 61.5l.3 .3M142.4 69l.3 .3M142.6 77.8l-.3 .2M142.6 60.6l-.3 .3M142.7 61.5l-.3 .3M142.7 69l-.3 .3"/>
<path d="M143 78.5l.3 .3M143.3 78.5l-.3 .3M143.8 76.7l.3 .2M144.1 76.7l-.3 .2M144.4 74.9l.3 .3M144.7 74.9l-.3 .3M144.8 67l.3 .3M144.9 73.4l.3 .3M145.1 67l-.3 .3M145.2 64.9l.2 .3M145.2 73.4l-.3 .3M145.2 72.6l.3 .3"/>
<path d="M145.3 60.6l.3 .3M145.4 64.9l-.2 .3M145.5 72.6l-.3 .3M145.6 60.6l-.3 .3M146.3 61.1l.2 .3M146.5 61.1l-.2 .3M146.8 74.2l.3 .3M146.8 61.8l.3 .3M146.9 60.4l.3 .3M147.1 74.2l-.3 .3M147.1 61.8l-.3 .3M147.2 60.4l-.3 .3"/>
<path d="M147.3 72.9l.3 .2M147.4 68.8l.3 .3M147.6 72.9l-.3 .2M147.7 68.8l-.3 .3M147.7 60.1l.3 .3M148 60.1l-.3 .3M148.2 66.3l.3 .2M148.3 75l.3 .3M148.3 70.3l.3 .3M148.5 66.3l-.3 .2M148.5 60.7l.3 .3M148.6 75l-.3 .3"/>
<path d="M148.6 70.3l-.3 .3M148.6 65.3l.3 .3M148.8 60.7l-.3 .3M148.9 65.3l-.3 .3M149.4 70.8l.3 .3M149.7 70.8l-.3 .3M150.5 66.1l.3 .3M150.6 78.3l.3 .3M150.8 66.1l-.3 .3M150.9 78.3l-.3 .3M151 74.2l.3 .3M151 72.2l.3 .3"/>
<path d="M151.2 77.4l.3 .3M151.3 74.2l-.3 .3M151.3 72.2l-.3 .3M151.5 77.4l-.3 .3M152 72.3l.3 .3M152.3 72.3l-.3 .3M153 66.3l.3 .3M153 71.3l.3 .3M153.3 66.3l-.3 .3M153.3 71.3l-.3 .3M153.3 64.4l.3 .3M153.6 64.4l-.3 .3"/>
<path d="M154.2 72.4l.3 .2M154.5 72.4l-.3 .2M154.9 73.1l.3 .3M155.1 73.9l.3 .3M155.2 73.1l-.3 .3M155.4 73.9l-.3 .3M156.1 60.1l.3 .3M156.4 60.1l-.3 .3M156.7 68.7l.3 .3M156.8 61.1l.3 .3M157 68.7l-.3 .3M157.1 61.1l-.3 .3"/>
<path d="M157.1 77.4l.3 .3M157.2 65l.3 .3M157.2 70.3l.3 .3M157.2 79l.3 .3M157.4 77.4l-.3 .3M157.4 65.9l.3 .2M157.5 65l-.3 .3M157.5 70.3l-.3 .3M157.5 79l-.3 .3M157.7 65.9l-.3 .2M158.4 63.7l.3 .3M158.6 61.8l.3 .3"/>
<path d="M158.7 63.7l-.3 .3M158.9 61.8l-.3 .3M159.4 70.8l.3 .3M159.4 67l.3 .3M159.6 63l.3 .3M159.7 77.9l.3 .3M159.7 70.8l-.3 .3M159.7 67l-.3 .3M159.9 63l-.3 .3M160 77.9l-.3 .3M160.8 66.3l.3 .3M160.9 74.7l.3 .3"/>
<path d="M161.1 66.3l-.3 .3M161.2 74.7l-.3 .3M163 64.6l.3 .3M163.3 64.6l-.3 .3M163.3 65.6l.3 .3M163.6 65.6l-.3 .3M164 62.7l.3 .3M164.3 62.7l-.3 .3M166.8 73.8l.3 .3M167.1 73.8l-.3 .3M169.4 72.9h.5M169.7 72.6v.6"/>
<path d="M169.7 79.8v.5M170.9 79.8h.5M171.2 79.6v.5M174.4 77.2l.3 .3M174.7 77.2l-.3 .3M175.4 76.5l.3 .3M175.7 76.5l-.3 .3M178.4 77.1l.3 .3M178.7 77.1l-.3 .3M179.3 76.4l.3 .3M179.6 76.4l-.3 .3M179.8 70.2l.3 .2"/>
<path d="M180.1 70.2l-.3 .2M181.4 74.4l.3 .3M181.7 74.4l-.3 .3M182.5 74.8l.3 .3M182.8 74.8l-.3 .3M184.2 78.4l.3 .3M184.5 78.4l-.3 .3M187 79.1l.2 .3M187.2 79.1l-.2 .3M188.2 76.4l.3 .3M188.5 76.4l-.3 .3M189.4 64.6l.7 .8"/>
<path d="M189.4 65h.7M189.8 64.6v.8M189.9 75.3l.3 .3M190.1 71.7l.3 .3M190.1 64.6l-.7 .8M190.2 75.3l-.3 .3M190.4 71.7l-.3 .3M190.6 68.8l.3 .3M190.9 69.5l.2 .3M190.9 68.8l-.3 .3M191.1 69.5l-.2 .3M191.3 79.9l.3 .3"/>
<path d="M191.6 79.9l-.3 .3M191.7 70.3l.3 .3M192 70.3l-.3 .3M192.5 74.5l.3 .3M192.6 71.8l.3 .3M192.8 74.5l-.3 .3M192.9 71.8l-.3 .3M194.1 65h.7M194.1 64.6l.7 .8M194.4 64.6v.8M194.8 64.6l-.7 .8M195.1 68.1l.3 .3"/>
<path d="M195.4 68.1l-.3 .3M195.9 70.7l.3 .3M196.2 70.7l-.3 .3M196.5 61.4l.3 .3M196.8 61.4l-.3 .3M197.4 60.7h.5M197.6 60.5v.5M197.7 73.8l.3 .3M198 73.8l-.3 .3M198.5 64.8l.3 .3M198.7 73.8l.3 .3M198.8 64.8l-.3 .3"/>
<path d="M198.8 65.6l.3 .3M199 73.8l-.3 .3M199.1 65.6l-.3 .3M200.6 68.8l.3 .3M200.9 79.2l.3 .3M200.9 68.8l-.3 .3M201 76.1l.3 .3M201.2 79.2l-.3 .3M201.3 76.1l-.3 .3M202.1 68.7l.3 .3M202.4 68.7l-.3 .3M202.6 73.5l.3 .3"/>
<path d="M202.9 73.5l-.3 .3M203.7 73.4h.5M203.9 73.2v.5M204 78.4l.3 .3M204 79.2l.3 .3M204.2 63.7l.7 .7M204.2 64h.7M204.3 78.4l-.3 .3M204.3 79.2l-.3 .3M204.6 63.7v.7M204.9 72.2h.6M204.9 63.7l-.7 .7"/>
<path d="M205.2 72v.5M96.2 98.5l.3 .3M96.5 98.5l-.3 .3M97.6 95.6l.3 .3M97.9 95.6l-.3 .3M98.1 98.3l.2 .3M98.3 98.3l-.2 .3M99 98.2l.3 .2M99.3 98.2l-.3 .2M99.9 80.1h.5M100.3 92.3h.5M100.6 92v.5"/>
<path d="M101.8 92.8h.5M102.1 92.5v.5M102.6 80.3h.5M102.8 80.1v.5M102.9 88.4l.3 .3M102.9 96.7l.3 .3M103.1 81.6h.5M103.2 88.4l-.3 .3M103.2 96.7l-.3 .3M103.2 99.8l.3 .3M103.3 98.2l.3 .2M103.3 81.4v.5"/>
<path d="M103.5 99.8l-.3 .3M103.6 98.2l-.3 .2M103.8 98.8l.3 .3M104.1 98.8l-.3 .3M105.1 96.1l.3 .2M105.4 96.1l-.3 .2M106.1 90.1l.7 .7M106.1 97.7l.7 .7M106.2 90.2h.5v.5h-.5zM106.2 97.8h.5v.5h-.5zM106.8 90.1l-.7 .7M106.8 97.7l-.7 .7"/>
<path d="M106.9 85.3l.3 .3M107 96.3l.3 .3M107.2 85.3l-.3 .3M107.3 96.3l-.3 .3M107.9 86.4l.7 .7M107.9 94l.7 .7M108 80.8l.3 .3M108 86.5h.5v.5h-.5zM108 94.1h.5v.5h-.5zM108.1 90.3l.3 .3M108.3 80.8l-.3 .3M108.4 90.3l-.3 .3"/>
<path d="M108.6 86.4l-.7 .7M108.6 94l-.7 .7M109.5 87.4l.3 .2M109.8 90.1l.7 .7M109.8 97.7l.7 .7M109.8 87.4l-.3 .2M109.9 90.2h.5v.5h-.5zM109.9 97.8h.5v.5h-.5zM110.3 88.8l.3 .3M110.5 90.1l-.7 .7M110.5 97.7l-.7 .7M110.6 88.8l-.3 .3"/>
<path d="M110.8 85.4l.3 .3M111.1 85.4l-.3 .3M111.1 91.4l.3 .3M111.4 91.4l-.3 .3M111.7 82.8l.3 .2M112 82.8l-.3 .2M112.3 99.1l.3 .3M112.6 99.1l-.3 .3M114.8 90.1l.7 .7M114.8 97.7l.7 .7M114.9 90.2h.5v.5h-.5zM114.9 97.8h.5v.5h-.5z"/>
<path d="M115.5 90.1l-.7 .7M115.5 97.7l-.7 .7M116.6 86.4l.8 .7M116.6 94l.8 .7M116.7 86.5h.6v.5h-.6zM116.7 94.1h.6v.5h-.6zM117 80.5l.3 .3M117.3 80.5l-.3 .3M117.4 86.4l-.8 .7M117.4 94l-.8 .7M118.5 90.1l.7 .7M118.5 97.7l.7 .7"/>
<path d="M118.6 90.2h.5v.5h-.5zM118.6 97.8h.5v.5h-.5zM119.2 97.7l-.7 .7M119.2 90.1l-.7 .7M119.8 85.4l.3 .3M120.1 85.4l-.3 .3M122.8 85.4l.3 .3M123.1 81.2l.3 .3M123.1 85.4l-.3 .3M123.4 81.2l-.3 .3M123.5 90.1l.7 .7M123.6 90.2h.5v.5h-.5z"/>
<path d="M124.2 90.1l-.7 .7M125.3 86.4l.8 .7M125.5 86.5h.5v.5h-.5zM126 99.3l.3 .2M126.1 86.4l-.8 .7M126.2 91.8l.3 .3M126.3 99.3l-.3 .2M126.5 91.8l-.3 .3M126.9 88.4l.3 .3M127.2 90.1l.7 .7M127.2 88.4l-.3 .3M127.3 90.2h.5v.5h-.5z"/>
<path d="M127.9 90.1l-.7 .7M128.1 82.9h.5M128.4 82.6v.5M129.2 83.2l.3 .3M129.5 83.2l-.3 .3M131.1 93.3l.3 .3M131.4 93.3l-.3 .3M131.5 99.2h.5M131.7 99v.5M132 94.5l.3 .3M132.3 94.5l-.3 .3M132.4 84.2l.3 .3"/>
<path d="M132.6 96.6l.3 .3M132.7 84.2l-.3 .3M132.7 93.4l.3 .3M132.9 96.6l-.3 .3M133 93.4l-.3 .3M133 90.4l.3 .3M133.3 90.4l-.3 .3M134.3 82.2h.5M134.5 99.6l.3 .3M134.5 81.9v.5M134.8 99.6l-.3 .3M137.5 99l.3 .3"/>
<path d="M137.6 83.5l.3 .3M137.8 99l-.3 .3M137.9 83.5l-.3 .3M138.6 93.4l.3 .3M138.9 93.4l-.3 .3M139.2 84.1l.3 .3M139.5 84.1l-.3 .3M140.3 89.7l.3 .3M140.6 89.7l-.3 .3M141.8 80.5h.5M141.9 90.1l.3 .3M142.1 86.8l.2 .3"/>
<path d="M142.1 80.2v.5M142.2 90.1l-.3 .3M142.3 86.8l-.2 .3M143 99.3l.3 .3M143.2 81.3h.5M143.3 99.3l-.3 .3M143.5 94l.3 .2M143.5 81v.5M143.8 94l-.3 .2M144.1 94.5l.3 .3M144.4 94.5l-.3 .3M144.4 91.1l.3 .3"/>
<path d="M144.7 91.1l-.3 .3M145.4 93.3l.3 .3M145.7 93.3l-.3 .3M145.9 94l.3 .3M146.2 94l-.3 .3M146.4 94.7l.3 .3M146.7 94.7l-.3 .3M150 97.8l.3 .3M150.3 97.8l-.3 .3M150.5 96.9l.3 .3M150.8 96.9l-.3 .3M151 87.6l.3 .3"/>
<path d="M151 95.7l.3 .3M151 82.6l.3 .3M151 86.7l.3 .3M151.3 87.6l-.3 .3M151.3 95.7l-.3 .3M151.3 82.6l-.3 .3M151.3 86.7l-.3 .3M151.8 95.2l.3 .3M152 83.1l.3 .3M152.1 95.2l-.3 .3M152.3 83.1l-.3 .3M152.6 96.1l.3 .3"/>
<path d="M152.9 96.1l-.3 .3M153.6 90.3l.3 .3M153.9 90.3l-.3 .3M153.9 95.7l.3 .3M154.2 95.7l-.3 .3M154.5 83.2l.3 .2M154.7 96.2l.3 .3M154.8 83.2l-.3 .2M154.8 94.5l.3 .3M155 96.2l-.3 .3M155.1 94.5l-.3 .3M155.4 86.8l.3 .3"/>
<path d="M155.4 83.3l.3 .3M155.4 92.4l.3 .3M155.4 99.4l.3 .3M155.7 86.8l-.3 .3M155.7 83.3l-.3 .3M155.7 92.4l-.3 .3M155.7 99.4l-.3 .3M155.9 96.2l.3 .3M156.1 90h.5M156.2 96.2l-.3 .3M156.3 85.6l.3 .3M156.3 89.7v.5"/>
<path d="M156.6 85.6l-.3 .3M157.2 86.5l.3 .3M157.3 92.5l.3 .3M157.3 85.6l.3 .3M157.5 86.5l-.3 .3M157.6 92.5l-.3 .3M157.6 85.6l-.3 .3M157.6 95.4l.3 .3M157.9 95.4l-.3 .3M157.9 98.8h.5M158.2 98.6v.5M158.2 97.1l.3 .3"/>
<path d="M158.5 97.1l-.3 .3M158.5 82.1l.3 .3M158.6 94.1l.3 .3M158.8 82.1l-.3 .3M158.9 96.6l.3 .3M158.9 94.1l-.3 .3M159.2 96.6l-.3 .3M159.2 91.7l.3 .3M159.2 88.2l.3 .3M159.2 90.9l.3 .3M159.4 99.7l.3 .3M159.5 91.7l-.3 .3"/>
<path d="M159.5 88.2l-.3 .3M159.5 90.9l-.3 .3M159.5 82l.3 .3M159.7 99.7l-.3 .3M159.7 95.7l.3 .3M159.8 82l-.3 .3M160 95.7l-.3 .3M160.1 85.4l.3 .3M160.3 96.2l.3 .3M160.4 85.4l-.3 .3M160.6 96.2l-.3 .3M160.7 83.3l.3 .3"/>
<path d="M161 83.3l-.3 .3M161.6 85.8l.3 .3M161.7 92.4l.3 .3M161.9 85.8l-.3 .3M162 92.4l-.3 .3M162.4 86.5l.3 .3M162.7 86.5l-.3 .3M162.7 94.9l.3 .3M163 94.9l-.3 .3M163.3 86.1l.3 .3M163.5 94.9l.3 .3M163.6 86.1l-.3 .3"/>
<path d="M163.8 94.9l-.3 .3M164.3 85.5l.3 .3M164.6 85.5l-.3 .3M165.2 85.3l.3 .3M165.3 90.9l.3 .3M165.5 85.3l-.3 .3M165.6 90.9l-.3 .3M166.1 95.4l.3 .3M166.4 95.4l-.3 .3M167.1 90h.5M167.3 89.7v.5M167.7 98.8h.5"/>
<path d="M168 98.6v.5M168 82.9l.3 .3M168.3 82.9l-.3 .3M168.4 84.1h.6M168.5 93.2l.3 .3M168.7 83.8v.5M168.8 93.2l-.3 .3M169.4 80.1h.5M169.8 89.2l.3 .3M169.8 92.2l.3 .3M169.8 94l.3 .2M170.1 89.2l-.3 .3"/>
<path d="M170.1 92.2l-.3 .3M170.1 94l-.3 .2M171 91.3l.3 .3M171.3 91.3l-.3 .3M171.5 94.4l.2 .3M171.5 82.5h.6M171.7 94.4l-.2 .3M171.8 82.3v.5M172.3 94.9l.3 .3M172.6 85.5l.3 .3M172.6 94.9l-.3 .3M172.9 85.5l-.3 .3"/>
<path d="M173 94.5l.3 .3M173.3 94.5l-.3 .3M173.5 89.2l.3 .3M173.6 83.5l.2 .3M173.8 89.2l-.3 .3M173.8 83.5l-.2 .3M174.2 92.5l.3 .3M174.2 86l.3 .3M174.5 92.5l-.3 .3M174.5 86l-.3 .3M175.3 86.5l.3 .3M175.6 86.5l-.3 .3"/>
<path d="M175.8 92.6l.3 .3M176.1 92.6l-.3 .3M176.3 94.9l.3 .3M176.4 86.2l.3 .3M176.6 94.9l-.3 .3M176.7 86.2l-.3 .3M176.7 92.5l.3 .3M177 92.5l-.3 .3M177.2 86.8l.3 .3M177.5 86.8l-.3 .3M177.5 83.2l.3 .3M177.5 95.4l.3 .3"/>
<path d="M177.6 98.8h.5M177.7 90.1h.5M177.8 83.2l-.3 .3M177.8 95.4l-.3 .3M177.9 98.6v.5M177.9 89.9v.5M179.2 87.6l.3 .3M179.5 87.6l-.3 .3M179.6 93l.3 .3M179.6 94.9l.3 .3M179.7 88.4l.3 .3M179.8 85.8l.3 .3"/>
<path d="M179.9 93l-.3 .3M179.9 94.9l-.3 .3M180 88.4l-.3 .3M180.1 85.8l-.3 .3M180.3 87.6l.3 .3M180.5 96.7l.3 .3M180.6 87.6l-.3 .3M180.8 96.7l-.3 .3M181.2 84.7l.3 .3M181.5 84.7l-.3 .3M181.5 83.4l.3 .3M181.8 83.4l-.3 .3"/>
<path d="M181.9 96l.3 .3M181.9 97.2l.3 .3M182.1 82.8h.5M182.2 96l-.3 .3M182.2 97.2l-.3 .3M182.4 82.5v.5M182.6 85.8l.3 .3M182.6 99.8l.3 .3M182.7 90.7l.3 .3M182.9 85.8l-.3 .3M182.9 99.8l-.3 .3M183 90.7l-.3 .3"/>
<path d="M183.3 95.3l.3 .3M183.6 86.4l.2 .3M183.6 95.3l-.3 .3M183.6 94.6l.3 .3M183.8 82.8l.3 .3M183.8 86.4l-.2 .3M183.9 94.6l-.3 .3M184.1 82.8l-.3 .3M184.1 90.6l.3 .3M184.4 90.6l-.3 .3M184.5 86.6l.3 .3M184.7 96.2l.2 .3"/>
<path d="M184.8 86.6l-.3 .3M184.9 96.2l-.2 .3M185.2 86.3l.3 .2M185.3 80.3h.5M185.4 83.2l.3 .3M185.4 96.1l.3 .3M185.5 92.1l.2 .3M185.5 86.3l-.3 .2M185.6 80.1v.5M185.7 83.2l-.3 .3M185.7 96.1l-.3 .3M185.7 92.1l-.2 .3"/>
<path d="M186.1 94.8l.3 .3M186.3 82.5l.3 .3M186.3 87.1l.3 .3M186.4 94.8l-.3 .3M186.6 87.1l-.3 .3M186.6 82.5l-.3 .3M187.1 91l.3 .3M187.2 87.1l.3 .3M187.2 96l.3 .3M187.3 83.6l.3 .2M187.4 91l-.3 .3M187.5 96l-.3 .3"/>
<path d="M187.5 87.1l-.3 .3M187.6 83.6l-.3 .2M187.7 94.7l.3 .2M187.9 90.6l.3 .3M188 89.7h.5M188 94.7l-.3 .2M188.2 98.8h.5M188.2 85.6l.3 .3M188.2 90.6l-.3 .3M188.3 89.4v.5M188.4 98.6v.5M188.5 85.6l-.3 .3"/>
<path d="M188.7 94.3l.3 .3M188.7 96l.3 .3M189 94.3l-.3 .3M189 96l-.3 .3M189 82.2l.3 .3M189.2 84.8l.3 .3M189.3 82.2l-.3 .3M189.4 93.2l.3 .3M189.5 84.8l-.3 .3M189.5 82.9l.3 .3M189.7 93.2l-.3 .3M189.8 82.9l-.3 .3"/>
<path d="M189.8 87.9l.3 .3M190 84.7l.3 .3M190.1 87.9l-.3 .3M190.3 93.2l.3 .3M190.3 84.7l-.3 .3M190.4 97.6l.3 .3M190.6 93.2l-.3 .3M190.7 97.6l-.3 .3M191.2 81l.3 .3M191.5 81l-.3 .3M191.7 92.6l.3 .3M191.9 91.8l.3 .3"/>
<path d="M192 92.6l-.3 .3M192.2 91.8l-.3 .3M192.2 86.7l.3 .3M192.2 90.5l.3 .3M192.5 86.7l-.3 .3M192.5 90.5l-.3 .3M192.5 94.7l.3 .3M192.6 85.7l.3 .3M192.7 97.4l.3 .3M192.8 94.7l-.3 .3M192.9 85.7l-.3 .3M193 97.4l-.3 .3"/>
<path d="M193.4 92l.3 .3M193.7 92l-.3 .3M194 86.2l.3 .3M194.1 83.4l.3 .3M194.3 86.2l-.3 .3M194.4 83.4l-.3 .3M194.9 82.6l.3 .3M195 95.9l.3 .3M195.2 82.6l-.3 .3M195.3 95.9l-.3 .3M195.9 86.7l.3 .3M196 92.2l.3 .3"/>
<path d="M196.2 86.7l-.3 .3M196.3 92.2l-.3 .3M196.8 86.8l.3 .3M197.1 86.8l-.3 .3M197.5 91.6l.3 .3M197.8 91.6l-.3 .3M197.9 96.2l.3 .3M197.9 85.9l.3 .3M198.2 96.2l-.3 .3M198.2 85.9l-.3 .3M198.6 90.7h.5M198.8 98.8h.5"/>
<path d="M198.9 90.4v.5M199 98.6v.5M199.4 92.9l.3 .2M199.7 92.9l-.3 .2M200 90.8l.3 .3M200.1 93.4l.3 .3M200.2 97.5h.5M200.3 90.8l-.3 .3M200.4 87.9l.3 .3M200.4 93.4l-.3 .3M200.5 97.2v.6M200.5 84.4l.3 .3"/>
<path d="M200.7 87.9l-.3 .3M200.8 84.4l-.3 .3M200.9 93.8l.3 .3M201.2 93.8l-.3 .3M201.4 88l.3 .3M201.7 88l-.3 .3M202.2 95.5l.3 .3M202.5 95.5l-.3 .3M202.6 92.9l.3 .3M202.9 92.9l-.3 .3M203 92.2l.3 .3M203.3 92.2l-.3 .3"/>
<path d="M203.6 91.3l.3 .3M203.6 99.7l.3 .3M203.9 91.3l-.3 .3M203.9 99.7l-.3 .3M204 88.4l.3 .3M204 98.8h.5M204 83.7l.3 .3M204 84.9l.3 .2M204.2 98.6v.5M204.3 88.4l-.3 .3M204.3 83.7l-.3 .3M204.3 84.9l-.3 .2"/>
<path d="M204.3 89.7h.5M204.6 89.4v.5M96.1 104.1l.3 .3M96.4 104.1l-.3 .3M96.9 114.8h.5M97.2 114.5v.5M97.4 108.3h.5M97.5 113.3l.3 .3M97.7 108.1v.5M97.8 113.3l-.3 .3M97.9 115.6l.3 .3M98.2 103.7l.3 .3"/>
<path d="M98.2 106.6l.3 .3M98.2 115.6l-.3 .3M98.5 103.7l-.3 .3M98.5 106.6l-.3 .3M98.8 115.7l.3 .3M99.1 115.7l-.3 .3M99.4 118l.8 .7M99.5 118.1h.5v.5h-.5zM99.6 118l.2-.1 .3 .2v.4l-.2 .2-.4-.1zM100 112.5h.2l.1 .1v.5l-.1 .1-.3-.1zM100.1 112.6l.3 .2-.3 .3-.3-.3zM100.2 118l-.8 .7"/>
<path d="M100.3 100l.3 .3M100.6 100l-.3 .3M100.9 109l.3 .3M101.1 100.5l.3 .3M101.2 109l-.3 .3M101.2 101.7l.3 .3M101.4 100.5l-.3 .3M101.5 101.7l-.3 .3M102.1 118.9h.5M102.3 118.6v.5M102.9 109.2l.3 .3M103 104.1l.3 .2"/>
<path d="M103.2 112.8l.3-.2 .3 .2-.3 .3zM103.2 109.2l-.3 .3M103.3 104.1l-.3 .2M103.3 112.5h.2l.2 .1v.5l-.2 .1-.2-.1zM103.4 118l.8 .7M103.5 118.1h.6v.5h-.6zM103.6 118l.3-.1 .2 .2v.4l-.2 .2-.4-.1zM103.8 106.4l.3 .3M104.1 106.4l-.3 .3M104.2 118l-.8 .7M104.4 115.7l.3 .3M104.7 115.7l-.3 .3"/>
<path d="M105.1 106.6l.3 .3M105.4 106.6l-.3 .3M105.4 108.3l.3 .3M105.6 113.6h.5M105.7 108.3l-.3 .3M105.8 113.4v.5M106 111.6l.3 .3M106.1 105.3l.7 .7M106.2 105.4h.5v.5h-.5zM106.3 111.6l-.3 .3M106.4 114.6h.5M106.7 114.3v.5"/>
<path d="M106.7 100.3l.3 .3M106.8 105.3l-.7 .7M107 100.3l-.3 .3M107.8 106.4l.3 .3M107.9 101.6l.7 .7M108 101.7h.5v.5h-.5zM108.1 106.4l-.3 .3M108.6 117.5h.9M108.6 101.6l-.7 .7M109.1 117v.9M109.3 109.9l.3 .3M109.6 109.9l-.3 .3"/>
<path d="M109.8 105.3l.7 .7M109.8 102.6l.3 .3M109.9 105.4h.5v.5h-.5zM110.1 102.6l-.3 .3M110.5 105.3l-.7 .7M111 110.4l.3 .3M111.3 110.4l-.3 .3M111.4 102.7h.5M111.7 102.4v.6M112.2 117.5h1M112.5 106.6h.5M112.7 106.4v.5"/>
<path d="M112.7 117v.9M113.9 108.1h.5M114.1 107.9v.5M114.8 105.3l.7 .7M114.9 105.4h.5v.5h-.5zM115.5 105.3l-.7 .7M115.9 117.5h.9M116 106.4l.3 .3M116.3 106.4l-.3 .3M116.4 117v.9M116.6 101.6l.8 .7M116.7 101.7h.6v.5h-.6z"/>
<path d="M117.4 101.6l-.8 .7M118.2 103.1l.3 .3M118.3 110.3l.3 .3M118.5 103.1l-.3 .3M118.5 105.3l.7 .7M118.6 105.4h.5v.5h-.5zM118.6 110.3l-.3 .3M119.2 105.3l-.7 .7M120 104.8l.3 .3M120.3 104.8l-.3 .3M120.4 108.1l.3 .3M120.7 108.1l-.3 .3"/>
<path d="M121.2 100.2l.3 .3M121.5 110.3l.2 .3M121.5 100.2l-.3 .3M121.7 110.3l-.2 .3M122.9 117.5h1M123.4 117v.9M123.6 101h.6M123.9 100.7v.6M124 106.4l.3 .3M124.3 106.4l-.3 .3M125.6 107.8l.3 .3M125.9 107.8l-.3 .3"/>
<path d="M126.6 117.5h.9M126.7 106.3l.3 .3M127 117v.9M127 106.3l-.3 .3M127.2 102.5l.3 .3M127.5 102.5l-.3 .3M127.8 105.3l.3 .3M128.1 105.3l-.3 .3M129.5 109.2l.3 .3M129.8 109.2l-.3 .3M130.1 102.4l.3 .3M130.2 117.5h1"/>
<path d="M130.4 102.4l-.3 .3M130.7 110.4l.3 .3M130.7 117v.9M130.9 105.7l.3 .3M131 110.4l-.3 .3M131.2 105.7l-.3 .3M131.3 102.5h.6M131.5 110.9l.3 .3M131.6 102.3v.5M131.8 110.9l-.3 .3M132.2 107.7l.3 .3M132.5 107.7l-.3 .3"/>
<path d="M133.2 105.5l.3 .3M133.5 105.5l-.3 .3M134.2 103.1l.3 .3M134.2 110.2l.3 .3M134.3 107.1l.3 .3M134.5 103.1l-.3 .3M134.5 110.2l-.3 .3M134.6 107.1l-.3 .3M134.7 100.7l.3 .3M135 100.7l-.3 .3M135.8 109.8l.3 .3M136.1 109.8l-.3 .3"/>
<path d="M136.5 109.3l.3 .3M136.8 109.3l-.3 .3M137 109.9l.3 .3M137.3 117.5h.9M137.3 109.9l-.3 .3M137.4 114.7h.5M137.7 114.4v.5M137.7 117v.9M138.2 107.8l.3 .3M138.5 107.8l-.3 .3M140.4 103.1l.3 .3M140.6 109h.5"/>
<path d="M140.7 103.1l-.3 .3M140.9 108.7v.6M140.9 117.5h1M140.9 110.7l.3 .3M141 104.8l.3 .3M141.2 110.7l-.3 .3M141.3 104.8l-.3 .3M141.4 117v.9M141.6 107.9l.3 .3M141.9 107.9l-.3 .3M142.6 108.9h.5M142.8 108.6v.5"/>
<path d="M142.9 105h.5M143.1 104.7v.5M143.5 101.5l.3 .3M143.8 101.5l-.3 .3M144 103.8l.3 .3M144.3 103.8l-.3 .3M144.6 117.5h.9M145 117v.9M146.1 105.8l.3 .3M146.3 114.1l.3 .3M146.4 105.8l-.3 .3M146.6 114.1l-.3 .3"/>
<path d="M147 114.8l.3 .3M147.3 114.8l-.3 .3M147.5 110.4l.3 .3M147.8 108.1l.3 .3M147.8 110.4l-.3 .3M148.1 108.1l-.3 .3M148.2 109.9l.3 .3M148.4 103.8l.3 .3M148.5 109.9l-.3 .3M148.6 107.7l.2 .3M148.7 100.6l.3 .3M148.7 103.8l-.3 .3"/>
<path d="M148.8 107.7l-.2 .3M149 100.6l-.3 .3M149.3 111l.3 .3M149.3 107.5l.3 .3M149.6 107.5l-.3 .3M149.6 111l-.3 .3M150 116.8l.3 .3M150.3 116.8l-.3 .3M151 113.7l.8 .8M151 117.4l.8 .9M151.4 113.7l.4 .4-.4 .4-.4-.4zM151.4 117.4l.4 .5-.4 .4-.4-.4z"/>
<path d="M151.7 101.5l.3 .3M151.7 107.5l.3 .3M151.7 104.7l.3 .3M151.8 113.7l-.8 .8M151.8 117.4l-.8 .9M152 101.5l-.3 .3M152 107.5l-.3 .3M152 104.7l-.3 .3M152.7 109.2l.3 .3M152.9 113.7l.8 .8M153 109.2l-.3 .3M153.3 113.7l.4 .4-.4 .4-.4-.4z"/>
<path d="M153.7 113.7l-.8 .8M154.2 110.8l.3 .3M154.5 110.8l-.3 .3M154.5 105.3l.3 .3M154.7 117.4l.8 .9M154.7 113.7l.8 .8M154.8 105.3l-.3 .3M155.1 113.7l.4 .4-.4 .4-.4-.4zM155.1 117.4l.4 .5-.4 .4-.4-.4zM155.4 107.5l.3 .3M155.5 113.7l-.8 .8M155.5 117.4l-.8 .9"/>
<path d="M155.7 107.5l-.3 .3M156.4 108.8l.3 .3M156.7 108.8l-.3 .3M157.6 108.8l.3 .3M157.7 114.1l.4-.4 .4 .4-.4 .4zM157.7 117.9l.4-.5 .4 .5-.4 .4zM157.7 117.4l.8 .9M157.7 113.7l.8 .8M157.9 108.8l-.3 .3M158.3 102.7l.3 .3M158.5 113.7l-.8 .8M158.5 117.4l-.8 .9"/>
<path d="M158.5 107.4h.5M158.6 102.7l-.3 .3M158.8 107.1v.5M159 104.2l.2 .3M159.2 104.2l-.2 .3M159.5 114.1l.4-.4 .4 .4-.4 .4zM159.5 113.7l.8 .8M160 105.8l.3 .3M160.3 105.8l-.3 .3M160.3 102.2l.3 .3M160.3 113.7l-.8 .8M160.3 100.8l.3 .3"/>
<path d="M160.6 102.2l-.3 .3M160.6 100.8l-.3 .3M160.7 104.5l.3 .3M161 104.5l-.3 .3M161.2 109.3l.3 .2M161.4 114.1l.4-.4 .4 .4-.4 .4zM161.4 117.9l.4-.5 .4 .5-.4 .4zM161.4 117.4l.8 .9M161.4 113.7l.8 .8M161.5 109.3l-.3 .2M161.6 101l.3 .3M161.9 101l-.3 .3"/>
<path d="M162.2 113.7l-.8 .8M162.2 117.4l-.8 .9M162.4 101.6l.3 .3M162.7 101.6l-.3 .3M163.2 113.2l.3 .3M163.5 108.3l.3 .3M163.5 113.2l-.3 .3M163.8 108.3l-.3 .3M164.3 101.5l.3 .3M164.3 113.8l.8 .8M164.3 111.9l.8 .8M164.3 117.5l.8 .8"/>
<path d="M164.6 101.5l-.3 .3M164.7 111.9l.4 .4-.4 .4-.4-.4zM164.7 113.8l.4 .4-.4 .4-.4-.4zM164.7 117.5l.4 .4-.4 .4-.4-.4zM165.1 111.9l-.8 .8M165.1 113.8l-.8 .8M165.1 117.5l-.8 .8M165.2 101.8l.3 .3M165.3 115.5l.3 .3M165.5 101.8l-.3 .3M165.6 115.5l-.3 .3M166.2 113.8l.8 .8"/>
<path d="M166.2 111.9l.8 .8M166.3 117.4l.3 .2M166.6 111.9l.4 .4-.4 .4-.4-.4zM166.6 113.8l.4 .4-.4 .4-.4-.4zM166.6 117.4l-.3 .2M167 111.9l-.8 .8M167 113.8l-.8 .8M167.7 103.5l.3 .3M168 103.5l-.3 .3M168 117.5l.8 .8M168 111.9l.8 .8M168 113.8l.8 .8"/>
<path d="M168.4 111.9l.4 .4-.4 .4-.4-.4zM168.4 113.8l.4 .4-.4 .4-.4-.4zM168.4 117.5l.4 .4-.4 .4-.4-.4zM168.4 107.4h.6M168.6 103l.3 .3M168.7 107.1v.5M168.8 113.8l-.8 .8M168.8 111.9l-.8 .8M168.8 117.5l-.8 .8M168.9 103l-.3 .3M169 105.6l.3 .3M169.3 105.6l-.3 .3"/>
<path d="M169.5 113.1l.3 .3M169.8 113.1l-.3 .3M170 106.1l.3 .3M170 111.4l.3 .3M170.3 106.1l-.3 .3M170.3 111.4l-.3 .3M170.3 103.5l.3 .3M170.6 103.5l-.3 .3M171 114.1l.4-.4 .4 .4-.4 .4zM171 117.8l.4-.4 .4 .4-.4 .4zM171 113.7l.8 .8M171 117.4l.8 .8"/>
<path d="M171.1 112.1l.3 .3M171.3 104.5l.3 .3M171.4 112.1l-.3 .3M171.6 104.5l-.3 .3M171.8 117.4l-.8 .8M171.8 113.7l-.8 .8M172.3 101.3l.3 .3M172.6 101.3l-.3 .3M172.8 104.1l.3 .3M172.9 114.1l.4-.4 .4 .4-.4 .4zM172.9 113.7l.8 .8M173.1 104.1l-.3 .3"/>
<path d="M173.7 113.7l-.8 .8M173.9 101.3l.3 .3M174.2 101.3l-.3 .3M174.5 111.4l.3 .3M174.7 114.1l.4-.4 .4 .4-.4 .4zM174.7 117.8l.4-.4 .4 .4-.4 .4zM174.7 117.4l.8 .8M174.7 113.7l.8 .8M174.8 111.4l-.3 .3M174.9 101.3l.3 .3M175.2 101.3l-.3 .3M175.5 113.7l-.8 .8"/>
<path d="M175.5 117.4l-.8 .8M175.8 101.5l.3 .3M176.1 101.5l-.3 .3M176.5 113.6l.3 .3M176.7 103.7l.3 .3M176.8 113.6l-.3 .3M177 103.7l-.3 .3M177.6 112.3l.5-.4 .4 .4-.4 .4zM177.6 114.2l.5-.4 .4 .4-.4 .4zM177.6 117.9l.5-.4 .4 .4-.4 .4zM177.6 113.8l.9 .8M177.6 111.9l.9 .8"/>
<path d="M177.6 117.5l.9 .8M177.9 101l.3 .3M178.2 101l-.3 .3M178.5 111.9l-.9 .8M178.5 117.5l-.9 .8M178.5 113.8l-.9 .8M178.6 106l.3 .2M178.9 106l-.3 .2M178.9 107.4h.5M179.1 107.2v.5M179.2 106.3l.3 .3M179.5 112.3l.4-.4 .4 .4-.4 .4z"/>
<path d="M179.5 114.2l.4-.4 .4 .4-.4 .4zM179.5 113.8l.8 .8M179.5 111.9l.8 .8M179.5 106.3l-.3 .3M179.9 117.8l.3 .2M180.2 100.2l.3 .3M180.2 117.8l-.3 .2M180.3 111.9l-.8 .8M180.3 113.8l-.8 .8M180.4 106.3l.3 .3M180.5 100.2l-.3 .3M180.7 106.3l-.3 .3"/>
<path d="M181.2 101l.3 .3M181.2 100.2l.3 .3M181.4 112.3l.4-.4 .4 .4-.4 .4zM181.4 114.2l.4-.4 .4 .4-.4 .4zM181.4 117.9l.4-.4 .4 .4-.4 .4zM181.4 117.5l.8 .8M181.4 113.8l.8 .8M181.4 111.9l.8 .8M181.5 100.2l-.3 .3M181.5 101l-.3 .3M181.8 103.7l.3 .3M181.9 106.7l.3 .3"/>
<path d="M181.9 107.5l.3 .3M182.1 103.7l-.3 .3M182.1 115.7l.3 .3M182.2 113.8l-.8 .8M182.2 117.5l-.8 .8M182.2 111.9l-.8 .8M182.2 106.7l-.3 .3M182.2 107.5l-.3 .3M182.4 115.7l-.3 .3M182.6 110.8l.3 .3M182.9 118.1h.5M182.9 110.8l-.3 .3"/>
<path d="M183.1 117.8v.5M183.4 100.5l.3 .3M183.6 107.5l.2 .3M183.7 100.5l-.3 .3M183.8 107.5l-.2 .3M184.1 100.3l.3 .3M184.4 104.6l.3 .3M184.4 100.3l-.3 .3M184.5 101l.3 .3M184.7 104.6l-.3 .3M184.7 114.3l.7 .7M184.7 116.2l.7 .7"/>
<path d="M184.7 112.7l.3 .3M184.8 114.4h.5v.5h-.5zM184.8 116.3h.5v.5h-.5zM184.8 101l-.3 .3M185 112.7l-.3 .3M185.4 114.3l-.7 .7M185.4 116.2l-.7 .7M185.4 105.2l.3 .3M185.7 105.2l-.3 .3M186.1 111.2l.3 .3M186.4 111.2l-.3 .3M186.5 116.2l.8 .7"/>
<path d="M186.5 114.3l.8 .7M186.6 114.4h.5v.5h-.5zM186.6 116.3h.5v.5h-.5zM187.1 109.5l.3 .3M187.1 113l.3 .3M187.3 114.3l-.8 .7M187.3 116.2l-.8 .7M187.3 103.9l.3 .3M187.4 109.5l-.3 .3M187.4 113l-.3 .3M187.6 103.9l-.3 .3M187.8 105.2l.3 .3"/>
<path d="M188.1 105.2l-.3 .3M188.2 101.4l.3 .3M188.3 108.3h.5M188.5 101.4l-.3 .3M188.5 108v.5M188.8 112.5l.7 .8M188.8 114.4l.7 .7M188.8 116.3l.7 .7M188.9 112.7h.5v.5h-.5zM188.9 114.5h.5v.5h-.5zM188.9 116.4h.5v.5h-.5zM189.2 106.4l.3 .3"/>
<path d="M189.5 106.4l-.3 .3M189.5 112.5l-.7 .8M189.5 114.4l-.7 .7M189.5 116.3l-.7 .7M189.5 102.7l.3 .3M189.7 110l.3 .3M189.8 102.7l-.3 .3M190 110l-.3 .3M190.5 110l.3 .3M190.6 112.5l.8 .8M190.6 116.3l.8 .7M190.6 114.4l.8 .7"/>
<path d="M190.7 112.7h.5v.5h-.5zM190.7 114.5h.5v.5h-.5zM190.7 116.4h.5v.5h-.5zM190.8 110l-.3 .3M190.9 100.2l.3 .3M191.1 102.4l.3 .3M191.2 100.2l-.3 .3M191.4 112.5l-.8 .8M191.4 114.4l-.8 .7M191.4 116.3l-.8 .7M191.4 102.4l-.3 .3M191.4 110.2l.3 .3"/>
<path d="M191.5 100.7l.3 .2M191.7 110.2l-.3 .3M191.8 100.7l-.3 .2M192 105.9l.2 .3M192.1 110.9l.3 .2M192.1 106.8l.3 .3M192.2 105.9l-.2 .3M192.3 103.9l.3 .3M192.4 110.9l-.3 .2M192.4 106.8l-.3 .3M192.6 103.9l-.3 .3M192.6 117.6l.3 .3"/>
<path d="M192.9 117.6l-.3 .3M193.2 103.9l.3 .3M193.5 103.9l-.3 .3M195 100.7l.3 .2M195.3 100.7l-.3 .2M196 100.2l.3 .3M196.1 116.2h1M196.3 100.2l-.3 .3M196.6 115.7v1M197 103.9l.2 .3M197.1 117.6l.8 .8M197.2 117.8h.6v.5h-.6z"/>
<path d="M197.2 103.9l-.2 .3M197.9 101.4l.3 .3M197.9 117.6l-.8 .8M198.2 101.4l-.3 .3M198.4 104.5l.3 .3M198.7 104.5l-.3 .3M198.9 108.3h.5M199.2 108v.5M200.4 117.6l.7 .8M200.5 117.8h.5v.5h-.5zM201.1 102.2l.3 .3M201.1 117.6l-.7 .8"/>
<path d="M201.2 116.2h1M201.4 102.2l-.3 .3M201.7 115.7v1M202 100.8l.3 .3M202.1 109.2l.3 .2M202.3 100.8l-.3 .3M202.4 109.2l-.3 .2M202.7 103.4l.3 .3M203 103.4l-.3 .3M203.2 101.4l.3 .3M203.5 101.4l-.3 .3M203.7 108.3h.5"/>
<path d="M203.9 108v.5M89.6 137.1l.7 .8M89.6 137.5h.7M89.6 139l.7 .8M89.7 135.2l.6 .7M89.7 139.2h.5v.5h-.5zM89.7 133.6l.3-.3 .3 .3-.3 .3zM89.8 129.8h.5M89.9 131.5h.4v.4h-.4zM90 137.1v.8M90 125.8l.3 .3M90.1 129.5v.5"/>
<path d="M90.3 135.2l-.6 .7M90.3 139l-.7 .8M90.3 137.1l-.7 .8M90.3 125.8l-.3 .3M100.9 122.6l.4-.1 .3 .3-.1 .6h-.6M102.2 123.4v.1M102.2 122.6v.2M118.3 134.9l.5-.1 .3 .4-.9 1h.9M119 136.7h-.7v.7l.2-.2 .5 .1 .1 .2-.1 .5-.2 .1-.5-.1M119.5 127.7l.2-.2 .3 .1 .1 .9M119.5 127.1v1.4M119.6 125.1h.9l-.5 .6 .4 .1v.6l-.2 .2-.6-.2"/>
<path d="M120.4 129h-.7v.7l.2-.2 .5 .1 .1 .2-.1 .5-.2 .1-.5-.1M120.8 127.7l.2-.2 .4 .2 .1 .5-.2 .2-.3 .1-.2-.1zM120.9 135.4l.2-.2 .3 .1 .1 .9M120.9 137.3l.2-.1h.3l.1 .9M120.9 134.8v1.4M120.9 136.7v1.4M122.1 127.1v1.2l.2 .2M122.2 135.4l.2-.2 .4 .2 .1 .5-.2 .3h-.3l-.2-.1zM122.2 125.8l.3-.2 .3 .1 .1 .9M122.2 129.6l.3-.1h.3l.1 .9M122.2 137.2h.4l.3 .3v.4l-.3 .2h-.4l-.1-.2zM122.2 125.1v1.5"/>
<path d="M122.2 129v1.4M122.8 128l.7-.1-.1-.3-.4-.1-.2 .2 .1 .7h.5M123.5 134.8v1.2l.2 .2M123.5 136.7v1.2l.2 .2M123.6 125.8l.2-.2 .4 .2 .1 .5-.2 .2-.3 .1-.2-.2zM123.6 129.6l.2-.1 .4 .1 .1 .6-.2 .2h-.3l-.2-.1zM124.2 135.7l.7-.1-.1-.3-.4-.1-.2 .3 .1 .7h.5M124.2 137.7l.7-.2-.1-.3h-.4l-.2 .2 .1 .7h.5M124.6 127.6l-.3-.1-.2 .2v.3l.5 .1v.3h-.5M124.9 125.1v1.3l.2 .2M124.9 129v1.2l.2 .2M125.2 126.8a1.67 1.67 0 0 1 0 2.3"/>
<path d="M125.6 126.1l.7-.1-.1-.3-.4-.1-.2 .2v.7h.6M125.6 130l.7-.2-.1-.3h-.4l-.2 .2v.7h.6M126 135.3l-.4-.1-.2 .3 .1 .2 .5 .1v.4h-.6M126 137.2h-.4l-.2 .2 .1 .2 .5 .1v.4h-.6M126.4 131.8h1.1M126.6 134.6a1.67 1.67 0 0 1 0 2.2M126.6 136.5a1.67 1.67 0 0 1 0 2.2M127 131.3v1.1M127.4 125.7l-.4-.1-.2 .2 .1 .2 .5 .2v.3h-.6M127.4 129.5h-.4l-.2 .2 .1 .2 .5 .1v.4h-.6M127.8 133.7h1.1M127.9 124.9a1.67 1.67 0 0 1 0 2.2"/>
<path d="M127.9 128.8a1.67 1.67 0 0 1 0 2.2M128.4 133.2v1.1M129.2 139.5h1.1M129.6 130.8l-.3 1.1h.9M129.8 139v1.1M130 131.4v1M130.7 133l.5-.2 .3 .5-.9 1h.9M132.3 131.5l-.3-.1-.2 .2v.2l.5 .1v.4h-.5M132.8 138.6h-.7l-.1 .7 .3-.1h.4l.2 .2-.1 .5-.2 .2-.6-.2M133 130.9v1.3l.2 .2M133.7 133.4l-.3-.1-.2 .2v.2l.5 .2v.3h-.5M133.9 131.5l.3-.1 .3 .3v.4l-.3 .3-.3-.1-.2-.2z"/>
<path d="M134.4 132.8v1.3l.2 .2M134.9 131.4h.6M135.1 130.9v1.3l.4 .2M135.1 139.2l-.3-.1-.3 .2 .1 .2 .5 .2v.3h-.6M135.2 133.4l.4-.1 .3 .3v.4l-.3 .3-.4-.1-.1-.2zM135.8 138.6v1.3l.2 .2M136.3 133.3h.5M136.4 131.5l-.3-.1-.2 .2v.2l.5 .1v.4h-.5M136.5 132.8v1.3l.3 .2M136.6 139.2l.2-.1 .4 .1 .1 .6-.2 .2-.3 .1-.2-.2zM137 130.7a1.67 1.67 0 0 1 0 2.2M137.7 139.1h.5"/>
<path d="M137.8 133.4l-.3-.1-.2 .2v.2l.5 .2v.3h-.5M137.9 138.6v1.3l.3 .2M138.4 132.6a1.67 1.67 0 0 1 0 2.3M139.2 139.2l-.3-.1-.3 .2 .1 .2 .5 .2v.3h-.6M139.8 138.4a1.67 1.67 0 0 1 0 2.2M88.9 151.9l.7-.7 .7 .7-.7 .7zM88.9 151.9h1.4M89.2 149.7h1.1M89.3 147.5l.5-.5 .5 .5-.5 .5zM89.4 143.3h.9M89.4 149.3h.8v.8h-.8zM89.5 145h.7v.7h-.7z"/>
<path d="M89.5 140.9l.8 .8M89.6 151.2v1.4M89.8 149.1v1.1M89.9 142.8v1M89.9 140.9l.4 .4-.4 .4-.4-.4zM90.3 140.9l-.8 .8M118.2 140.5h1l-.6 1.5M118.2 144.6h1l-.6 1.4M118.3 144h.8M118.5 146.8l.1-.1a.78 .78 0 0 1 .5 .7 .78 .78 0 0 1-.5 .8 .97 .97 0 0 1-.1-1.4zM119.5 149.5l.2-.1h.3l.1 .9M119.5 151.7l.2-.1 .3 .1 .1 .9"/>
<path d="M119.5 148.9v1.4M119.5 151.1v1.5M120.9 141.2l.2-.2 .3 .1 .1 .9M120.9 143.1l.2-.1h.3l.1 1M120.9 145.2l.2-.1h.3l.1 .9M120.9 147.3l.2-.1 .3 .1 .1 .9M120.9 149.4h.3l.3 .2v.4l-.3 .3h-.3l-.2-.3zM120.9 151.7l.3-.1 .3 .3v.4l-.3 .3-.3-.1-.2-.2zM120.9 140.5v1.5M120.9 142.5v1.5M120.9 144.6v1.4M120.9 146.7v1.5"/>
<path d="M122.1 148.9v1.2l.2 .2M122.1 151.1v1.3l.2 .2M122.2 143.1l.2-.1 .4 .1 .1 .6-.2 .2-.3 .1-.2-.2zM122.2 141.1l.4-.1 .3 .3v.4l-.3 .3-.4-.1-.1-.2zM122.2 145.1h.4l.3 .3v.4l-.3 .2h-.4l-.1-.2zM122.2 147.3l.4-.1 .3 .3v.4l-.3 .3-.4-.1-.1-.2zM122.8 149.8l.7-.1-.1-.3h-.4l-.2 .2 .1 .7h.5M122.8 152.1l.7-.2-.1-.2-.4-.1-.2 .2 .1 .7h.5M123.5 140.5v1.3l.2 .2M123.5 142.5v1.2l.2 .3M123.5 144.6v1.2l.2 .2M123.5 146.7v1.2l.2 .3"/>
<path d="M124.2 141.5l.7-.1-.1-.3-.4-.1-.2 .2 .1 .7h.5M124.2 143.5l.7-.2-.1-.3h-.4l-.2 .2 .1 .7h.5M124.2 145.6l.7-.2-.1-.3h-.4l-.2 .2 .1 .7h.5M124.2 147.7l.7-.2-.1-.2-.4-.1-.2 .2 .1 .7h.5M124.6 149.4h-.3l-.2 .2v.2l.5 .1v.4h-.5M124.6 151.7l-.3-.1-.2 .2v.2l.5 .1v.4h-.5M125.2 148.7a1.67 1.67 0 0 1 0 2.2M125.2 150.9a1.67 1.67 0 0 1 0 2.2M126 141.1l-.4-.1-.2 .2 .1 .2 .5 .2v.3h-.6M126 143h-.4l-.2 .2 .1 .2 .5 .1v.4h-.6M126 145.1h-.4l-.2 .2 .1 .2 .5 .1v.4h-.6M126 147.3l-.4-.1-.2 .2 .1 .2 .5 .1v.4h-.6"/>
<path d="M126.6 140.3a1.67 1.67 0 0 1 0 2.3M126.6 142.3a1.67 1.67 0 0 1 0 2.2M126.6 144.4a1.67 1.67 0 0 1 0 2.2M126.6 146.5a1.67 1.67 0 0 1 0 2.2"/>
<circle cx="106.1" cy="18.4" r=".51"/>
<circle cx="111.6" cy="16.1" r=".51"/>
<circle cx="134.7" cy="18.2" r=".33"/>
<circle cx="134.7" cy="15.9" r=".33"/>
<circle cx="137" cy="18.2" r=".33"/>
<circle cx="137" cy="15.9" r=".33"/>
<circle cx="139.3" cy="18.2" r=".33"/>
<circle cx="139.3" cy="15.9" r=".33"/>
<circle cx="146.4" cy="17.7" r=".33"/>
<circle cx="148.7" cy="17.7" r=".33"/>
<circle cx="166.8" cy="14.7" r=".48"/>
<circle cx="168.7" cy="16.6" r=".48"/>
<circle cx="170.5" cy="7.3" r=".48"/>
<circle cx="172.4" cy="14.7" r=".48"/>
<circle cx="174.2" cy="7.3" r=".48"/>
<circle cx="176.1" cy="16.6" r=".48"/>
<circle cx="177.9" cy="14.7" r=".48"/>
<circle cx="182.9" cy="16.6" r=".48"/>
<circle cx="184.8" cy="14.7" r=".48"/>
<circle cx="186.7" cy="16.6" r=".48"/>
<circle cx="186.7" cy="7.3" r=".48"/>
<circle cx="188.5" cy="18.4" r=".48"/>
<circle cx="188.5" cy="14.7" r=".48"/>
<circle cx="190.4" cy="7.3" r=".48"/>
<circle cx="190.4" cy="16.6" r=".48"/>
<circle cx="192.2" cy="14.7" r=".48"/>
<circle cx="194.1" cy="16.6" r=".48"/>
<circle cx="106.1" cy="34.6" r=".51"/>
<circle cx="111.6" cy="20.8" r=".51"/>
<circle cx="111.6" cy="34.6" r=".51"/>
<circle cx="118.7" cy="35.3" r=".51"/>
<circle cx="123.3" cy="35.3" r=".51"/>
<circle cx="137.1" cy="35.3" r=".51"/>
<circle cx="146.4" cy="20" r=".33"/>
<circle cx="146.4" cy="22.4" r=".33"/>
<circle cx="148.7" cy="22.4" r=".33"/>
<circle cx="148.7" cy="20" r=".33"/>
<circle cx="194.3" cy="35.8" r=".15"/>
<circle cx="196.5" cy="35.8" r=".15"/>
<circle cx="121" cy="40.7" r=".51"/>
<circle cx="137.1" cy="40.7" r=".51"/>
<circle cx="109.1" cy="117.5" r=".47"/>
<circle cx="112.7" cy="117.5" r=".47"/>
<circle cx="116.4" cy="117.5" r=".47"/>
<circle cx="123.4" cy="117.5" r=".47"/>
<circle cx="127" cy="117.5" r=".47"/>
<circle cx="130.7" cy="117.5" r=".47"/>
<circle cx="137.7" cy="117.5" r=".47"/>
<circle cx="141.4" cy="117.5" r=".47"/>
<circle cx="145" cy="117.5" r=".47"/>
<circle cx="196.6" cy="116.2" r=".47"/>
<circle cx="201.7" cy="116.2" r=".47"/>
<circle cx="90" cy="135.6" r=".33"/>
<circle cx="90.2" cy="127.9" r=".15"/>
<circle cx="89.8" cy="147.5" r=".51"/>
<circle cx="89.8" cy="145.4" r=".48"/>
<circle cx="89.9" cy="143.3" r=".47"/>
</g>
<g fill="none" stroke="#000" stroke-width=".23">
<path d="M93.6 11.1h2.3M94.8 10l1.1 1.1-1.1 1.2-1.2-1.2zM94.8 10v2.3M111.8 11.1h2.4M113 10l1.2 1.1-1.2 1.2-1.2-1.2zM113 10v2.3M117.9 11.1l1.1-1.1 1.2 1.1-1.2 1.2zM117.9 11.1h2.3M119 10v2.3M136.1 11.1l1.2-1.1 1.2 1.1-1.2 1.2zM136.1 11.1h2.4M137.3 10v2.3"/>
<path d="M142.2 11.1l1.1-1.1 1.2 1.1-1.2 1.2zM142.2 11.1h2.3M143.3 10v2.3M160.4 11.1l1.2-1.1 1.2 1.1-1.2 1.2zM160.4 11.1h2.4M161.6 10v2.3"/>
</g>
<use href="#words"/>
</svg>
